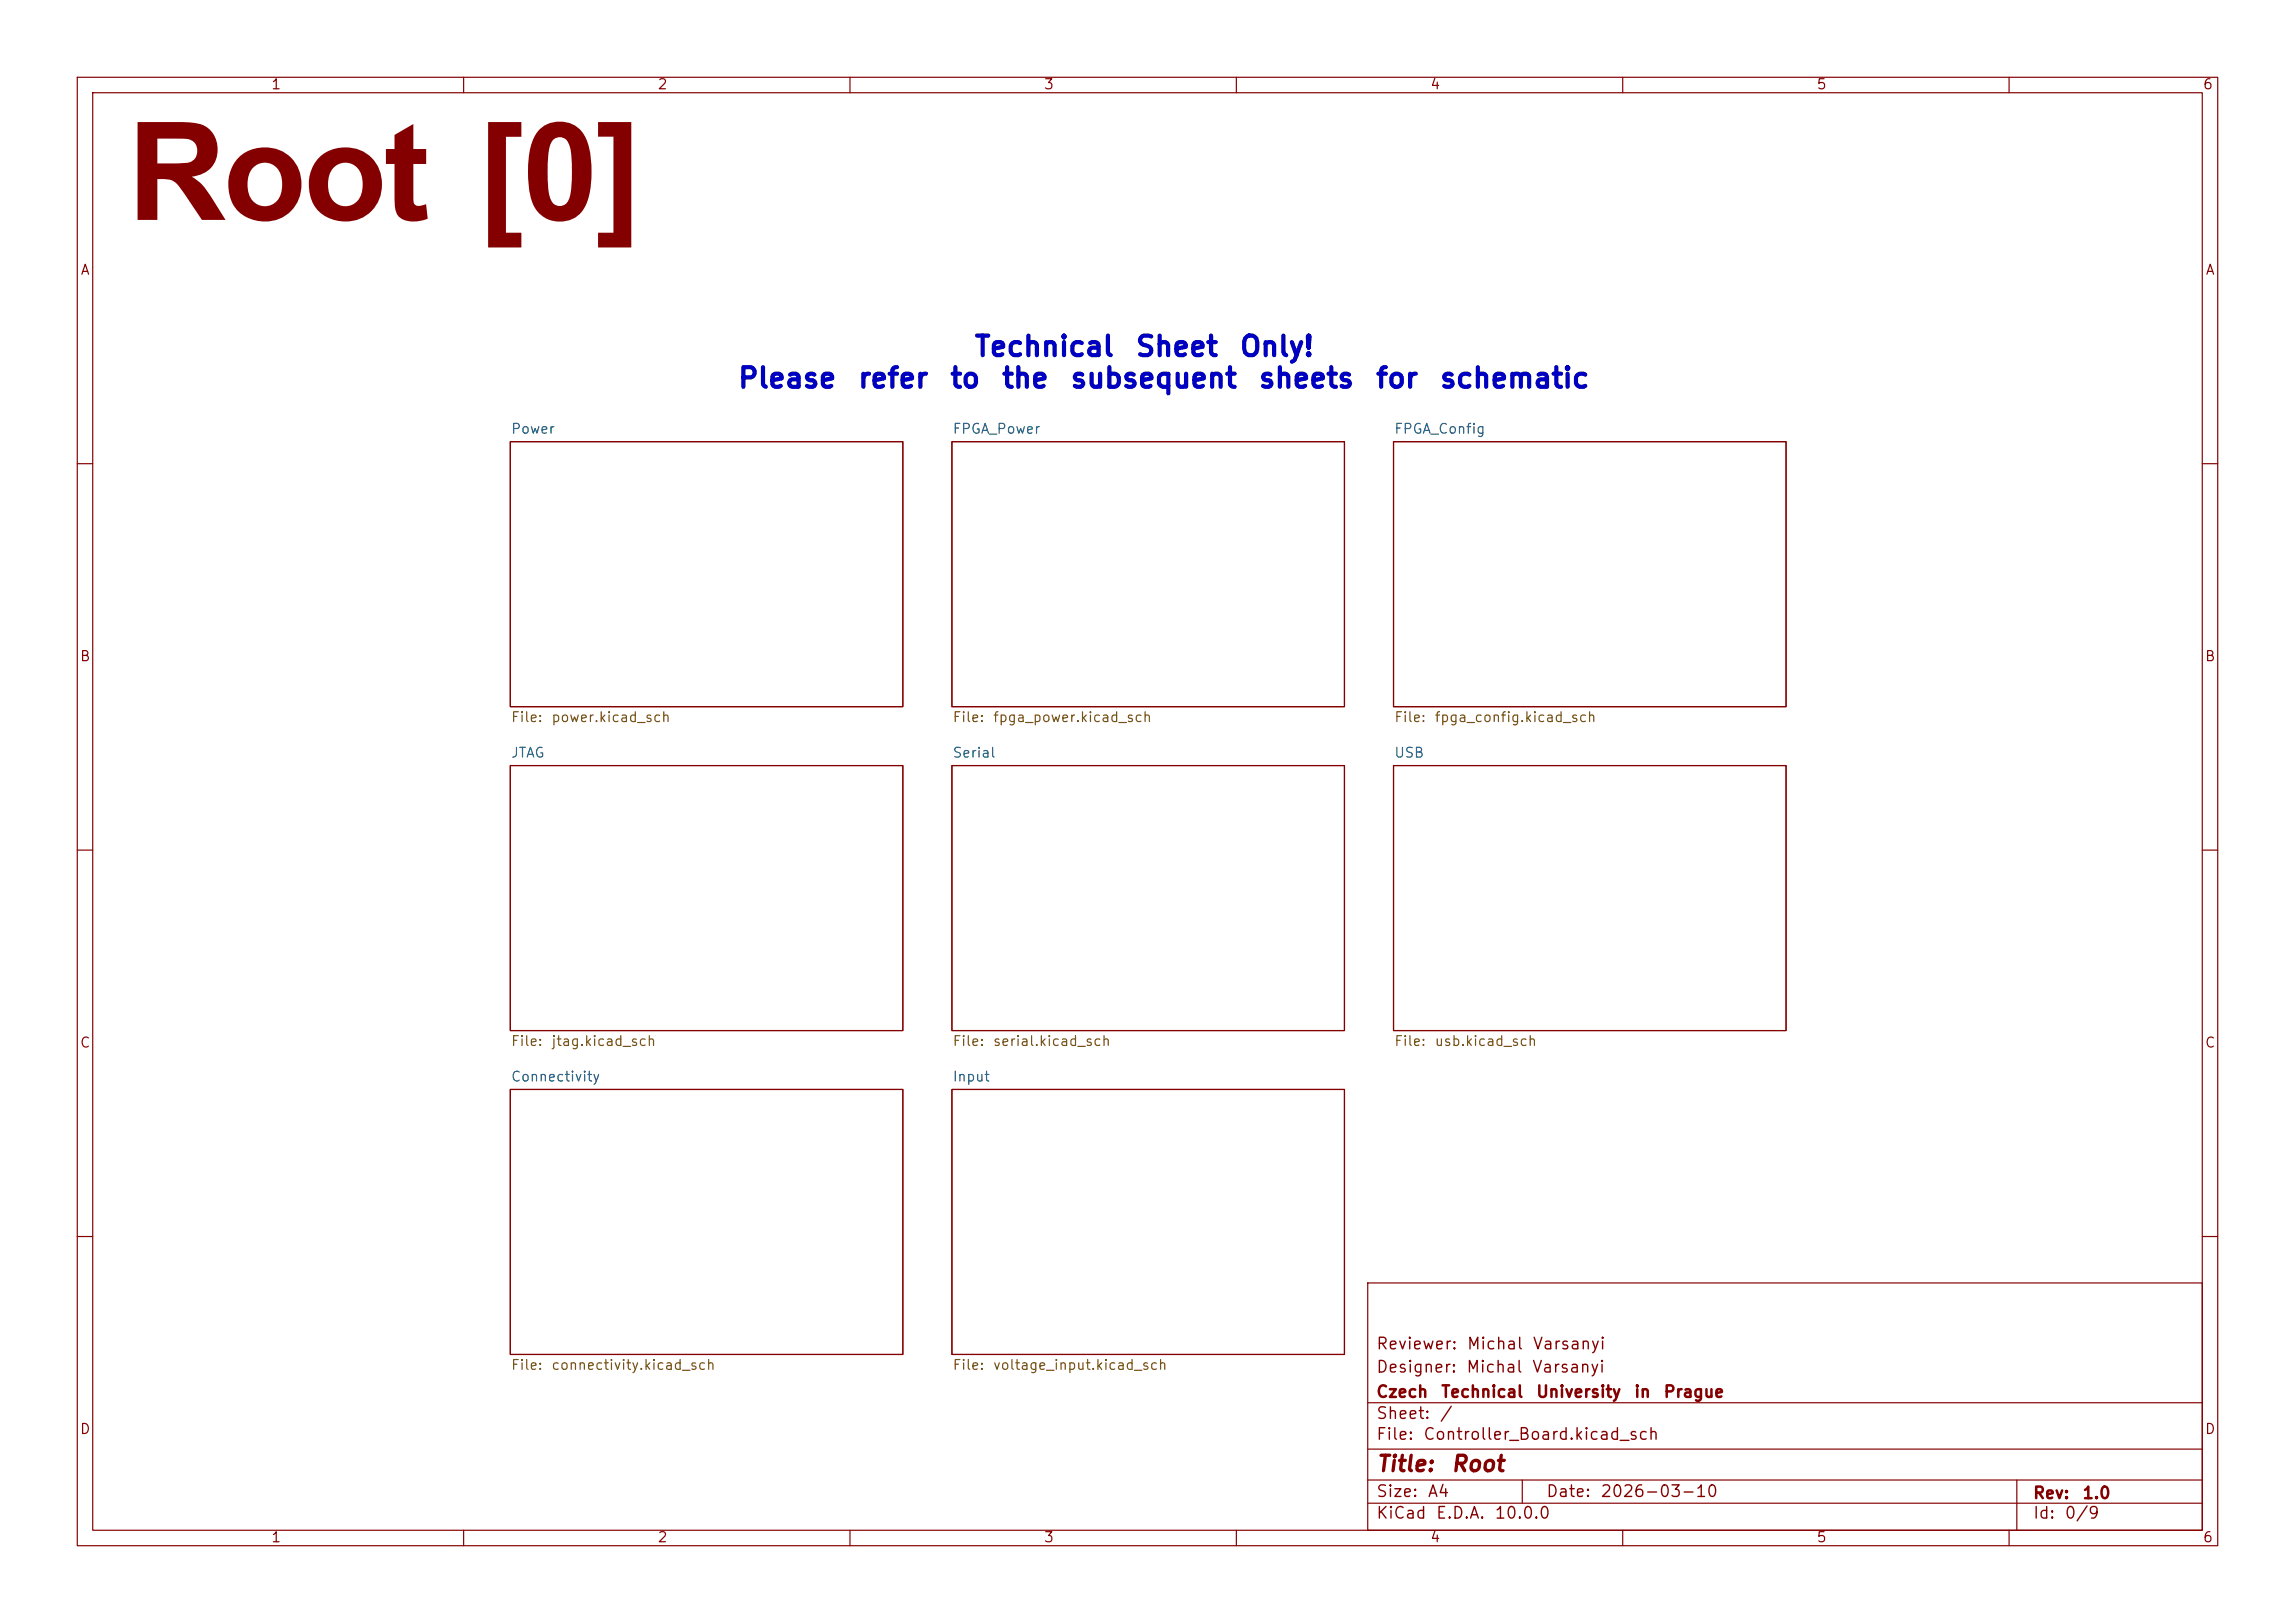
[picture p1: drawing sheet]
<svg xmlns="http://www.w3.org/2000/svg" width="297mm" height="210mm" viewBox="0 0 297 210" stroke-linecap="round" stroke-linejoin="round" font-family="sans-serif">
<defs><g id="words">
<text font-size="17.7" fill="#840000" x="16.5" y="28.5">Root [0]</text>
<g font-size="2.5" fill="#0000c2">
<text x="125.9" y="46.7">Technical</text>
<text x="146.8" y="46.7">Sheet</text>
<text x="160.3" y="46.7">Only!</text>
<text x="95.3" y="50.8">Please</text>
<text x="110.9" y="50.8">refer</text>
<text x="122.8" y="50.8">to</text>
<text x="129.5" y="50.8">the</text>
<text x="138.4" y="50.8">subsequent</text>
<text x="162.7" y="50.8">sheets</text>
<text x="177.9" y="50.8">for</text>
<text x="186.2" y="50.8">schematic</text>
</g>
<g font-size="2" fill="#840000">
<text x="178" y="190.9">Title:</text>
<text x="187.7" y="190.9">Root</text>
</g>
<g font-size="1.5" fill="#840000">
<text x="178" y="178">Designer:</text>
<text x="178" y="175">Reviewer:</text>
<text x="189.7" y="178">Michal</text>
<text x="189.7" y="175">Michal</text>
<text x="198.2" y="178">Varsanyi</text>
<text x="198.2" y="175">Varsanyi</text>
<text x="178" y="184">Sheet:</text>
<text x="178" y="181.2">Czech</text>
<text x="186.2" y="184">/</text>
<text x="186.4" y="181.2">Technical</text>
<text x="198.7" y="181.2">University</text>
<text x="211.4" y="181.2">in</text>
<text x="215.2" y="181.2">Prague</text>
<text x="178" y="186.7">File:</text>
<text x="184.1" y="186.7">Controller_Board.kicad_sch</text>
<text x="178" y="196.9">KiCad</text>
<text x="178" y="194.1">Size:</text>
<text x="184.7" y="194.1">A4</text>
<text x="185.7" y="196.9">E.D.A.</text>
<text x="193.3" y="196.9">10.0.0</text>
<text x="200" y="194.1">Date:</text>
<text x="207" y="194.1">2026-03-10</text>
<text x="263" y="194.3">Rev:</text>
<text x="263" y="196.9">Id:</text>
<text x="267.1" y="196.9">0/9</text>
<text x="269.4" y="194.3">1.0</text>
</g>
<g font-size="1.3" fill="#840000">
<text x="35" y="11.9">1</text>
<text x="85" y="11.9">2</text>
<text x="135" y="11.9">3</text>
<text x="185" y="11.9">4</text>
<text x="235" y="11.9">5</text>
<text x="285" y="11.9">6</text>
<text x="10.3" y="35.9">A</text>
<text x="285.3" y="35.9">A</text>
<text x="10.3" y="85.9">B</text>
<text x="285.3" y="85.9">B</text>
<text x="10.3" y="135.9">C</text>
<text x="285.3" y="135.9">C</text>
<text x="10.3" y="185.9">D</text>
<text x="285.3" y="185.9">D</text>
<text x="35" y="199.9">1</text>
<text x="85" y="199.9">2</text>
<text x="135" y="199.9">3</text>
<text x="185" y="199.9">4</text>
<text x="235" y="199.9">5</text>
<text x="285" y="199.9">6</text>
</g>
<g font-size="1.3" fill="#006464">
<text x="66" y="56.4">Power</text>
<text x="123.2" y="56.4">FPGA_Power</text>
<text x="180.3" y="56.4">FPGA_Config</text>
<text x="66" y="98.3">JTAG</text>
<text x="123.2" y="98.3">Serial</text>
<text x="180.3" y="98.3">USB</text>
<text x="66" y="140.3">Connectivity</text>
<text x="123.2" y="140.3">Input</text>
</g>
<g font-size="1.3" fill="#725600">
<text x="66" y="93.8">File:</text>
<text x="71.3" y="93.8">power.kicad_sch</text>
<text x="123.2" y="93.8">File:</text>
<text x="128.4" y="93.8">fpga_power.kicad_sch</text>
<text x="180.3" y="93.8">File:</text>
<text x="185.6" y="93.8">fpga_config.kicad_sch</text>
<text x="66" y="135.7">File:</text>
<text x="71.3" y="135.7">jtag.kicad_sch</text>
<text x="123.2" y="135.7">File:</text>
<text x="128.4" y="135.7">serial.kicad_sch</text>
<text x="180.3" y="135.7">File:</text>
<text x="185.6" y="135.7">usb.kicad_sch</text>
<text x="66" y="177.6">File:</text>
<text x="71.3" y="177.6">connectivity.kicad_sch</text>
<text x="123.2" y="177.6">File:</text>
<text x="128.4" y="177.6">voltage_input.kicad_sch</text>
</g>
</g></defs>
<g fill="none" stroke="#840000" stroke-width=".15">
<path d="M10 10h277v190h-277zM12 12h273v186h-273zM60 10v2M110 10v2M160 10v2M210 10v2M260 10v2M66 57.2h50.8v34.2h-50.8zM123.2 57.2h50.8v34.2h-50.8zM180.3 57.2h50.8v34.2h-50.8zM10 60h2M285 60h2"/>
<path d="M66 99.1h50.8v34.3h-50.8zM123.2 99.1h50.8v34.3h-50.8zM180.3 99.1h50.8v34.3h-50.8zM10 110h2M285 110h2M66 141h50.8v34.3h-50.8zM123.2 141h50.8v34.3h-50.8zM10 160h2M177 166h108v32h-108zM285 160h2M60 198v2M110 198v2"/>
<path d="M160 198v2M177 194.5h108M177 191.5h108M177 187.5h108M177 181.5h108M197 191.5v3M210 198v2M260 198v2M261 191.5v6.5"/>
</g>
<use href="#words"/>
</svg>
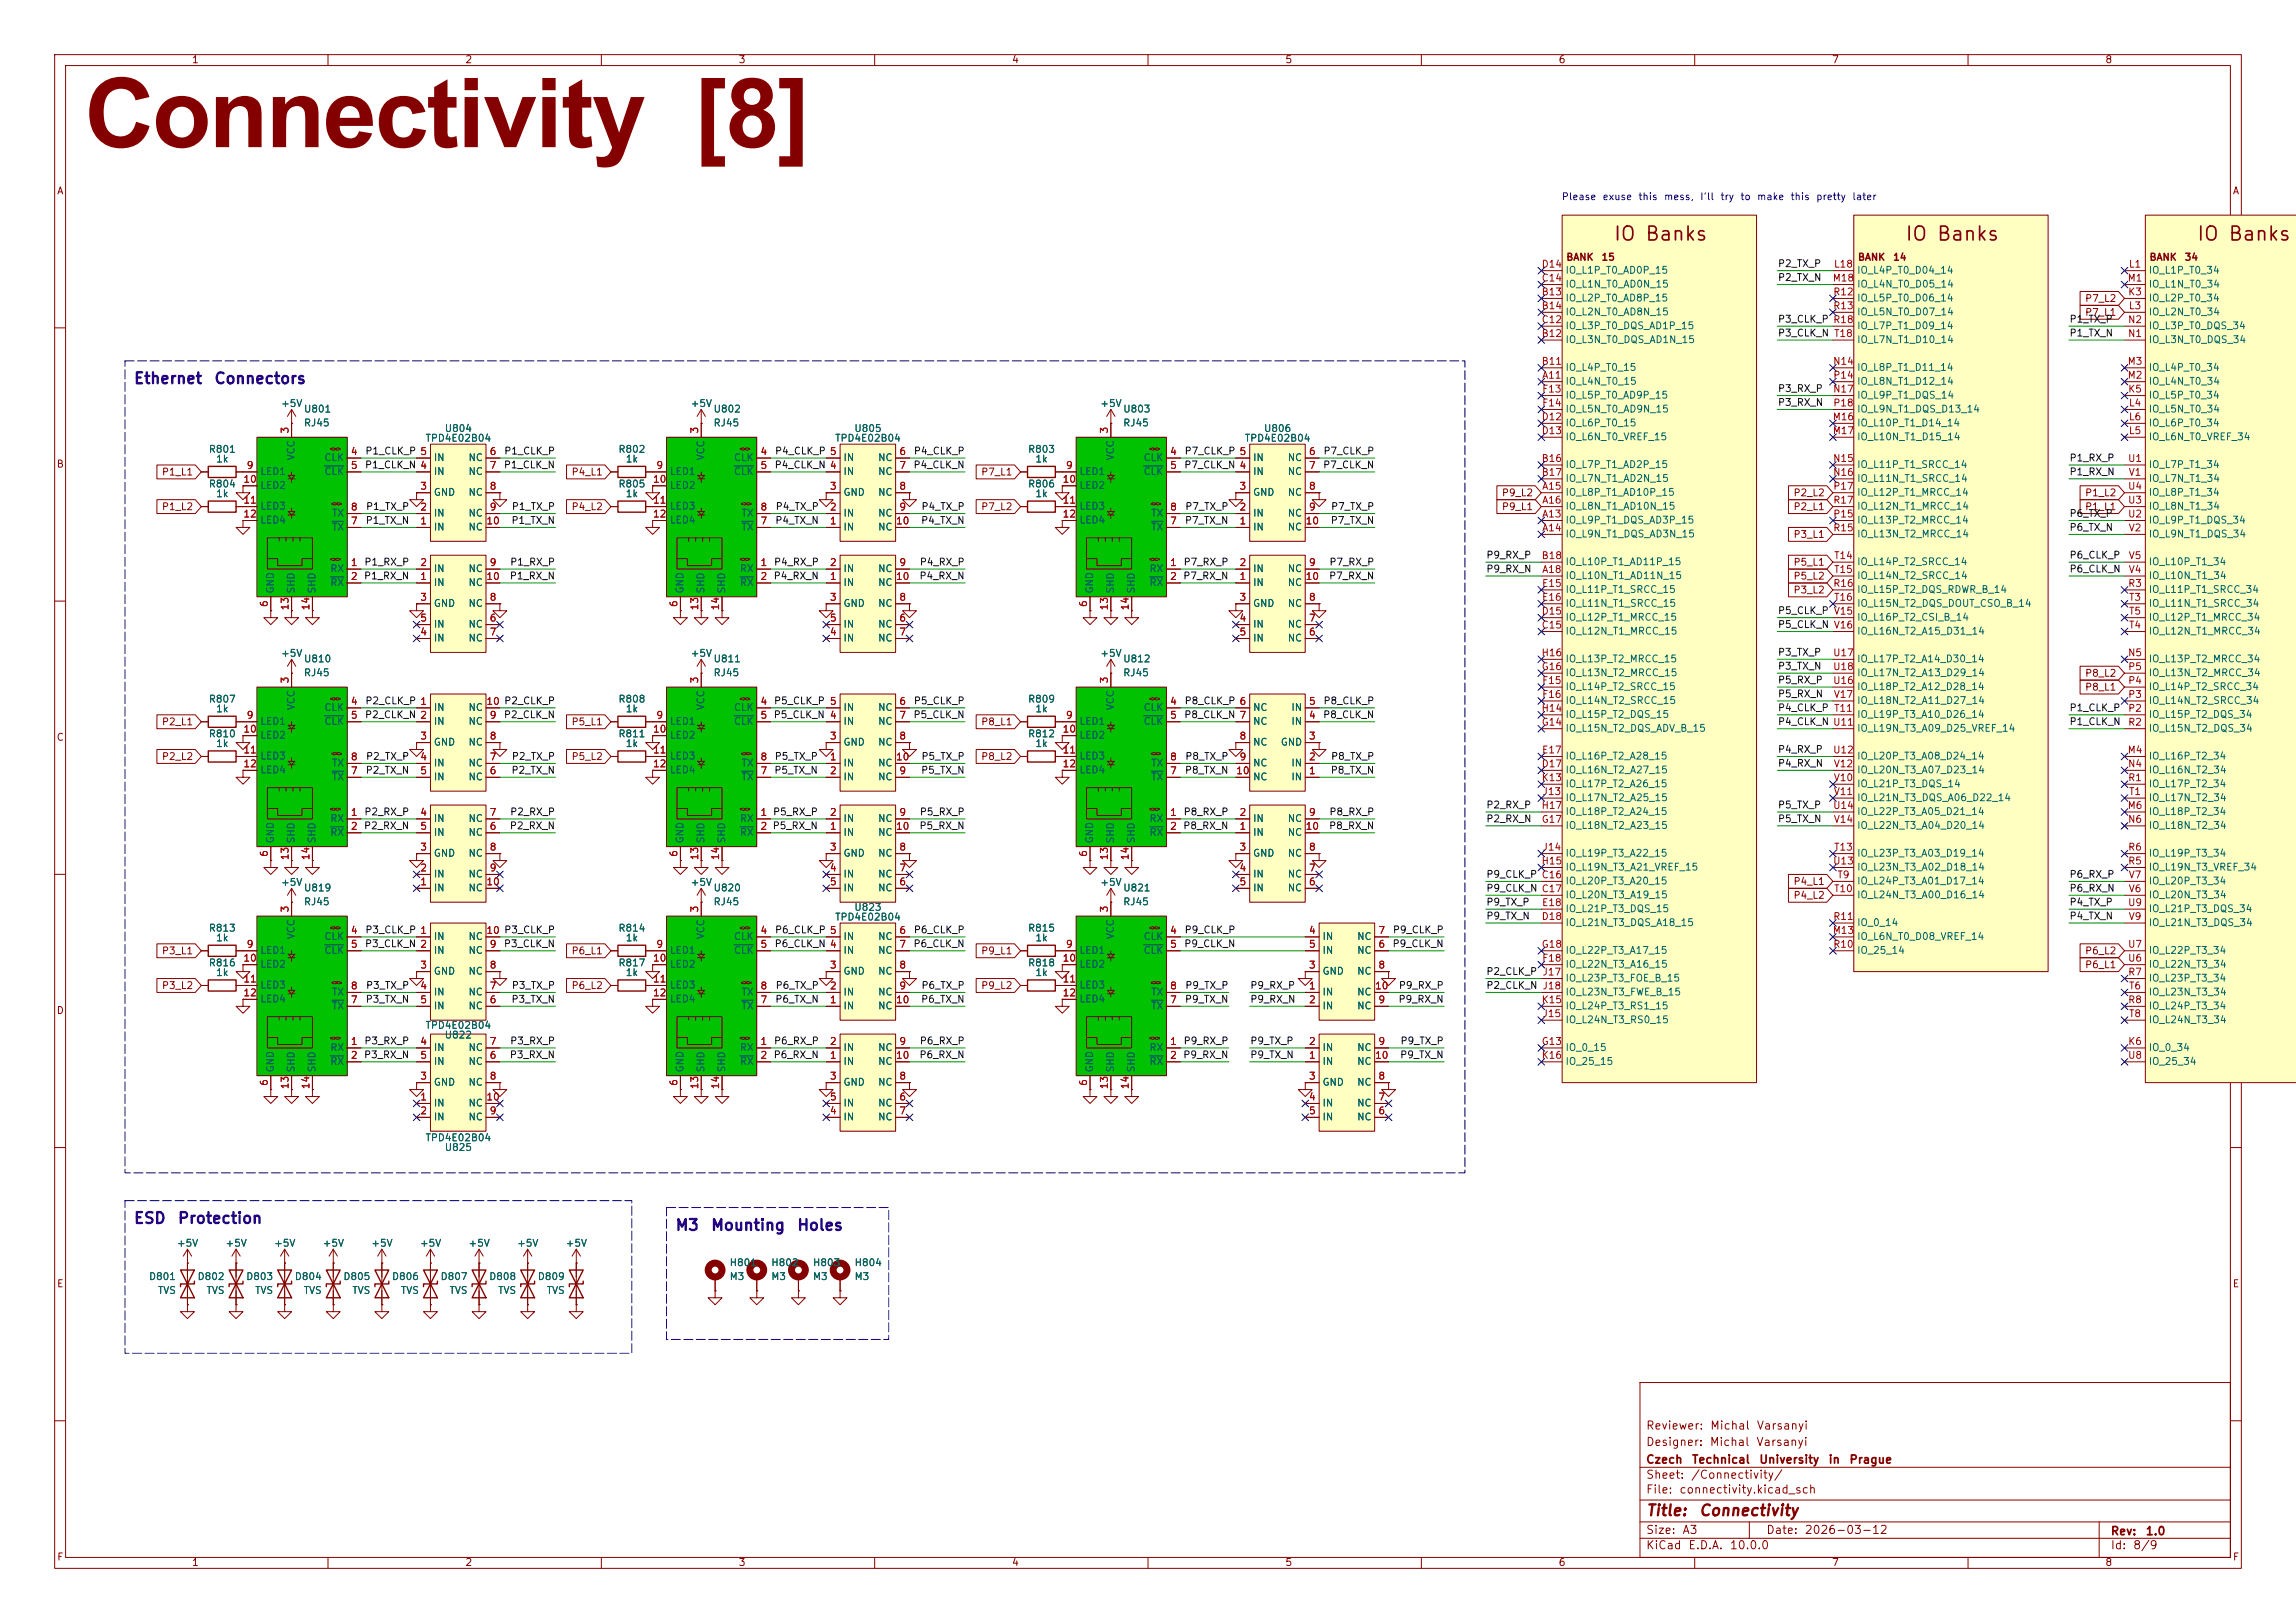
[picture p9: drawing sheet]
<svg xmlns="http://www.w3.org/2000/svg" width="420mm" height="297mm" viewBox="0 0 420 297" stroke-linecap="round" stroke-linejoin="round" font-family="sans-serif">
<defs><g id="words">
<text font-size="17.7" fill="#840000" x="15.5" y="26.9">Connectivity [8]</text>
<g font-size="2.5" fill="#840000">
<text x="295" y="44.7">IO</text>
<text x="300.8" y="44.7">Banks</text>
<text x="348.4" y="44.7">IO</text>
<text x="354.1" y="44.7">Banks</text>
<text x="401.7" y="44.7">IO</text>
<text x="407.5" y="44.7">Banks</text>
</g>
<g font-size="2" fill="#0000c2">
<text x="24.4" y="70.7">Ethernet</text>
<text x="39.1" y="70.7">Connectors</text>
<text x="24.4" y="224.4">ESD</text>
<text x="32.4" y="224.4">Protection</text>
<text x="123.4" y="225.7">M3</text>
<text x="129.9" y="225.7">Mounting</text>
<text x="145.7" y="225.7">Holes</text>
</g>
<g font-size="2" fill="#840000">
<text x="301" y="277.9">Title:</text>
<text x="310.6" y="277.9">Connectivity</text>
</g>
<g font-size="1.5" fill="#840000">
<text x="301" y="262">Reviewer:</text>
<text x="312.7" y="262">Michal</text>
<text x="321.2" y="262">Varsanyi</text>
<text x="301" y="268.2">Czech</text>
<text x="301" y="265">Designer:</text>
<text x="309.4" y="268.2">Technical</text>
<text x="312.6" y="265">Michal</text>
<text x="321.2" y="265">Varsanyi</text>
<text x="321.7" y="268.2">University</text>
<text x="334.4" y="268.2">in</text>
<text x="338.2" y="268.2">Prague</text>
<text x="301" y="273.7">File:</text>
<text x="301" y="271">Sheet:</text>
<text x="307.1" y="273.7">connectivity.kicad_sch</text>
<text x="309.2" y="271">/Connectivity/</text>
<text x="301" y="281.1">Size:</text>
<text x="307.6" y="281.1">A3</text>
<text x="323" y="281.1">Date:</text>
<text x="330" y="281.1">2026-03-12</text>
<text x="386" y="281.3">Rev:</text>
<text x="392.4" y="281.3">1.0</text>
<text x="301" y="283.9">KiCad</text>
<text x="308.7" y="283.9">E.D.A.</text>
<text x="316.3" y="283.9">10.0.0</text>
<text x="386" y="283.9">Id:</text>
<text x="390.1" y="283.9">8/9</text>
</g>
<g font-size="1.3" fill="#840000">
<text x="35" y="11.9">1</text>
<text x="85" y="11.9">2</text>
<text x="135" y="11.9">3</text>
<text x="185" y="11.9">4</text>
<text x="235" y="11.9">5</text>
<text x="285" y="11.9">6</text>
<text x="335" y="11.9">7</text>
<text x="385" y="11.9">8</text>
<text x="10.3" y="35.9">A</text>
<text x="408.3" y="35.9">A</text>
<text x="286.4" y="48">BANK</text>
<text x="292.8" y="48">15</text>
<text x="339.7" y="48">BANK</text>
<text x="346.2" y="48">14</text>
<text x="393.1" y="48">BANK</text>
<text x="399.5" y="48">34</text>
<text x="381.3" y="55.6">P7_L2</text>
<text x="381.3" y="58.1">P7_L1</text>
<text x="10.3" y="85.9">B</text>
<text x="29.5" y="87.3">P1_L1</text>
<text x="104.4" y="87.3">P4_L1</text>
<text x="179.4" y="87.3">P7_L1</text>
<text x="29.5" y="93.7">P1_L2</text>
<text x="104.4" y="93.7">P4_L2</text>
<text x="179.4" y="93.7">P7_L2</text>
<text x="274.6" y="91.1">P9_L2</text>
<text x="274.6" y="93.7">P9_L1</text>
<text x="328" y="93.7">P2_L1</text>
<text x="328" y="91.1">P2_L2</text>
<text x="381.3" y="91.1">P1_L2</text>
<text x="381.3" y="93.7">P1_L1</text>
<text x="328" y="98.7">P3_L1</text>
<text x="328" y="103.8">P5_L1</text>
<text x="328" y="106.4">P5_L2</text>
<text x="328" y="108.9">P3_L2</text>
<text x="381.3" y="124.1">P8_L2</text>
<text x="381.3" y="126.7">P8_L1</text>
<text x="10.3" y="135.9">C</text>
<text x="29.5" y="133">P2_L1</text>
<text x="104.4" y="133">P5_L1</text>
<text x="179.4" y="133">P8_L1</text>
<text x="408.2" y="135.9">C</text>
<text x="29.5" y="139.4">P2_L2</text>
<text x="104.4" y="139.4">P5_L2</text>
<text x="179.4" y="139.4">P8_L2</text>
<text x="328" y="164.8">P4_L2</text>
<text x="328" y="162.2">P4_L1</text>
<text x="29.5" y="174.9">P3_L1</text>
<text x="104.4" y="174.9">P6_L1</text>
<text x="179.4" y="174.9">P9_L1</text>
<text x="381.3" y="174.9">P6_L2</text>
<text x="381.3" y="177.5">P6_L1</text>
<text x="10.3" y="185.9">D</text>
<text x="29.5" y="181.3">P3_L2</text>
<text x="104.4" y="181.3">P6_L2</text>
<text x="179.4" y="181.3">P9_L2</text>
<text x="10.3" y="235.9">E</text>
<text x="408.3" y="235.9">E</text>
<text x="10.3" y="285.9">F</text>
<text x="35" y="286.9">1</text>
<text x="85" y="286.9">2</text>
<text x="135" y="286.9">3</text>
<text x="185" y="286.9">4</text>
<text x="235" y="286.9">5</text>
<text x="285" y="286.9">6</text>
<text x="335" y="286.9">7</text>
<text x="385" y="286.9">8</text>
<text x="408.3" y="285.9">F</text>
</g>
<g font-size="1.3" fill="#0000c2">
<text x="285.6" y="36.9">Please</text>
<text x="293" y="36.9">exuse</text>
<text x="299.6" y="36.9">this</text>
<text x="304.3" y="36.9">mess,</text>
<text x="310.9" y="36.9">I'll</text>
<text x="314.6" y="36.9">try</text>
<text x="318.2" y="36.9">to</text>
<text x="321.3" y="36.9">make</text>
<text x="327.4" y="36.9">this</text>
<text x="332.1" y="36.9">pretty</text>
<text x="338.7" y="36.9">later</text>
</g>
<g font-size="1.3" fill="#a90000">
<text x="281.9" y="51.8">C14</text>
<text x="281.9" y="49.3">D14</text>
<text x="335.1" y="51.8">M18</text>
<text x="335.4" y="49.3">L18</text>
<text x="389.1" y="51.8">M1</text>
<text x="389.3" y="49.3">L1</text>
<text x="281.9" y="54.4">B13</text>
<text x="281.9" y="56.9">B14</text>
<text x="281.9" y="59.4">C12</text>
<text x="335.2" y="54.4">R12</text>
<text x="335.2" y="56.9">R13</text>
<text x="389.2" y="59.4">N2</text>
<text x="389.2" y="54.4">K3</text>
<text x="389.3" y="56.9">L3</text>
<text x="281.9" y="62">B12</text>
<text x="335.4" y="62">T18</text>
<text x="389.2" y="62">N1</text>
<text x="281.9" y="67.1">B11</text>
<text x="282" y="69.6">A11</text>
<text x="335.2" y="67.1">N14</text>
<text x="335.2" y="69.6">P14</text>
<text x="389.1" y="69.6">M2</text>
<text x="389.1" y="67.1">M3</text>
<text x="281.9" y="77.2">D12</text>
<text x="282" y="72.1">F13</text>
<text x="282" y="74.7">F14</text>
<text x="335.1" y="77.2">M16</text>
<text x="335.2" y="72.1">N17</text>
<text x="335.2" y="74.7">P18</text>
<text x="389.2" y="72.1">K5</text>
<text x="389.3" y="74.7">L4</text>
<text x="389.3" y="77.2">L6</text>
<text x="53.1" y="79.4" transform="rotate(-90 53.1 79.4)">3</text>
<text x="64.1" y="83.6">4</text>
<text x="76.8" y="83.6">5</text>
<text x="89.5" y="83.6">6</text>
<text x="128" y="79.4" transform="rotate(-90 128 79.4)">3</text>
<text x="139" y="83.6">4</text>
<text x="151.7" y="83.6">5</text>
<text x="164.4" y="83.6">6</text>
<text x="202.9" y="79.4" transform="rotate(-90 202.9 79.4)">3</text>
<text x="213.9" y="83.6">4</text>
<text x="226.6" y="83.6">5</text>
<text x="239.3" y="83.6">6</text>
<text x="281.9" y="79.8">D13</text>
<text x="335.1" y="79.8">M17</text>
<text x="389.3" y="79.8">L5</text>
<text x="44.4" y="88.6">10</text>
<text x="45" y="86.1">9</text>
<text x="64.1" y="86.1">5</text>
<text x="76.8" y="89.9">3</text>
<text x="76.8" y="86.1">4</text>
<text x="89.5" y="86.1">7</text>
<text x="89.5" y="89.9">8</text>
<text x="119.3" y="88.6">10</text>
<text x="119.9" y="86.1">9</text>
<text x="139" y="86.1">5</text>
<text x="151.7" y="89.9">3</text>
<text x="151.7" y="86.1">4</text>
<text x="164.4" y="86.1">7</text>
<text x="164.4" y="89.9">8</text>
<text x="194.3" y="88.6">10</text>
<text x="194.9" y="86.1">9</text>
<text x="213.9" y="86.1">5</text>
<text x="226.6" y="89.9">3</text>
<text x="226.6" y="86.1">4</text>
<text x="239.3" y="86.1">7</text>
<text x="239.3" y="89.9">8</text>
<text x="281.9" y="84.8">B16</text>
<text x="281.9" y="87.4">B17</text>
<text x="282" y="89.9">A15</text>
<text x="335.2" y="84.8">N15</text>
<text x="335.2" y="87.4">N16</text>
<text x="335.2" y="89.9">P17</text>
<text x="389.2" y="84.8">U1</text>
<text x="389.2" y="89.9">U4</text>
<text x="389.3" y="87.4">V1</text>
<text x="44.4" y="92.5">11</text>
<text x="44.4" y="95">12</text>
<text x="64.1" y="93.7">8</text>
<text x="76.8" y="93.7">2</text>
<text x="89.5" y="93.7">9</text>
<text x="119.3" y="92.5">11</text>
<text x="119.3" y="95">12</text>
<text x="139" y="93.7">8</text>
<text x="151.7" y="93.7">2</text>
<text x="164.4" y="93.7">9</text>
<text x="194.3" y="92.5">11</text>
<text x="194.3" y="95">12</text>
<text x="213.9" y="93.7">8</text>
<text x="226.6" y="93.7">2</text>
<text x="239.3" y="93.7">9</text>
<text x="282" y="95">A13</text>
<text x="282" y="92.5">A16</text>
<text x="335.2" y="95">P15</text>
<text x="335.2" y="92.5">R17</text>
<text x="389.2" y="95">U2</text>
<text x="389.2" y="92.5">U3</text>
<text x="64.1" y="96.3">7</text>
<text x="76.8" y="96.3">1</text>
<text x="88.9" y="96.3">10</text>
<text x="139" y="96.3">7</text>
<text x="151.7" y="96.3">1</text>
<text x="163.8" y="96.3">10</text>
<text x="213.9" y="96.3">7</text>
<text x="226.6" y="96.3">1</text>
<text x="238.7" y="96.3">10</text>
<text x="282" y="97.5">A14</text>
<text x="335.2" y="97.5">R15</text>
<text x="389.3" y="97.5">V2</text>
<text x="64.1" y="103.9">1</text>
<text x="64.1" y="106.4">2</text>
<text x="76.8" y="106.4">1</text>
<text x="76.8" y="103.9">2</text>
<text x="88.9" y="106.4">10</text>
<text x="89.5" y="103.9">9</text>
<text x="139" y="103.9">1</text>
<text x="139" y="106.4">2</text>
<text x="151.7" y="106.4">1</text>
<text x="151.7" y="103.9">2</text>
<text x="163.8" y="106.4">10</text>
<text x="164.4" y="103.9">9</text>
<text x="213.9" y="103.9">1</text>
<text x="213.9" y="106.4">2</text>
<text x="226.6" y="106.4">1</text>
<text x="226.6" y="103.9">2</text>
<text x="238.7" y="106.4">10</text>
<text x="239.3" y="103.9">9</text>
<text x="281.9" y="102.6">B18</text>
<text x="282" y="107.7">E15</text>
<text x="282" y="105.2">A18</text>
<text x="335.2" y="107.7">R16</text>
<text x="335.4" y="102.6">T14</text>
<text x="335.4" y="105.2">T15</text>
<text x="389.2" y="107.7">R3</text>
<text x="389.3" y="105.2">V4</text>
<text x="389.3" y="102.6">V5</text>
<text x="49.3" y="111.2" transform="rotate(-90 49.3 111.2)">6</text>
<text x="53.1" y="111.8" transform="rotate(-90 53.1 111.8)">13</text>
<text x="56.9" y="111.8" transform="rotate(-90 56.9 111.8)">14</text>
<text x="76.8" y="110.2">3</text>
<text x="89.5" y="110.2">8</text>
<text x="124.2" y="111.2" transform="rotate(-90 124.2 111.2)">6</text>
<text x="128" y="111.8" transform="rotate(-90 128 111.8)">13</text>
<text x="131.8" y="111.8" transform="rotate(-90 131.8 111.8)">14</text>
<text x="151.7" y="110.2">3</text>
<text x="164.4" y="110.2">8</text>
<text x="199.1" y="111.2" transform="rotate(-90 199.1 111.2)">6</text>
<text x="202.9" y="111.8" transform="rotate(-90 202.9 111.8)">13</text>
<text x="206.8" y="111.8" transform="rotate(-90 206.8 111.8)">14</text>
<text x="226.6" y="110.2">3</text>
<text x="239.3" y="110.2">8</text>
<text x="281.9" y="112.8">D15</text>
<text x="282" y="110.2">E16</text>
<text x="335.3" y="112.8">V15</text>
<text x="335.4" y="110.2">T16</text>
<text x="389.3" y="110.2">T3</text>
<text x="389.3" y="112.8">T5</text>
<text x="76.8" y="116.6">4</text>
<text x="76.8" y="114">5</text>
<text x="89.5" y="114">6</text>
<text x="89.5" y="116.6">7</text>
<text x="151.7" y="116.6">4</text>
<text x="151.7" y="114">5</text>
<text x="164.4" y="114">6</text>
<text x="164.4" y="116.6">7</text>
<text x="226.6" y="114">4</text>
<text x="226.6" y="116.6">5</text>
<text x="239.3" y="116.6">6</text>
<text x="239.3" y="114">7</text>
<text x="281.9" y="115.3">C15</text>
<text x="335.3" y="115.3">V16</text>
<text x="389.3" y="115.3">T4</text>
<text x="53.1" y="125.2" transform="rotate(-90 53.1 125.2)">3</text>
<text x="128" y="125.2" transform="rotate(-90 128 125.2)">3</text>
<text x="202.9" y="125.2" transform="rotate(-90 202.9 125.2)">3</text>
<text x="281.9" y="120.4">H16</text>
<text x="281.9" y="122.9">G16</text>
<text x="282" y="125.5">F15</text>
<text x="335.2" y="125.5">U16</text>
<text x="335.2" y="120.4">U17</text>
<text x="335.2" y="122.9">U18</text>
<text x="389.2" y="120.4">N5</text>
<text x="389.2" y="125.5">P4</text>
<text x="389.2" y="122.9">P5</text>
<text x="45" y="131.8">9</text>
<text x="64.1" y="129.3">4</text>
<text x="64.1" y="131.8">5</text>
<text x="76.8" y="129.3">1</text>
<text x="76.8" y="131.8">2</text>
<text x="88.9" y="129.3">10 P2_CLK_P</text>
<text x="88.9" y="129.3">10</text>
<text x="89.5" y="131.8">9</text>
<text x="119.9" y="131.8">9</text>
<text x="139" y="129.3">4</text>
<text x="139" y="131.8">5</text>
<text x="151.7" y="131.8">4</text>
<text x="151.7" y="129.3">5</text>
<text x="164.4" y="129.3">6</text>
<text x="164.4" y="131.8">7</text>
<text x="194.9" y="131.8">9</text>
<text x="213.9" y="129.3">4</text>
<text x="213.9" y="131.8">5</text>
<text x="226.6" y="129.3">6</text>
<text x="226.6" y="131.8">7</text>
<text x="239.3" y="131.8">4</text>
<text x="239.3" y="129.3">5</text>
<text x="281.9" y="130.6">H14</text>
<text x="282" y="128">F16</text>
<text x="335.3" y="128">V17</text>
<text x="335.4" y="130.6">T11</text>
<text x="389.2" y="130.6">P2</text>
<text x="389.2" y="128">P3</text>
<text x="44.4" y="134.4">10</text>
<text x="76.8" y="135.6">3</text>
<text x="89.5" y="135.6">8</text>
<text x="119.3" y="134.4">10</text>
<text x="151.7" y="135.6">3</text>
<text x="164.4" y="135.6">8</text>
<text x="194.3" y="134.4">10</text>
<text x="226.6" y="135.6">8</text>
<text x="239.3" y="135.6">3</text>
<text x="281.9" y="133.1">G14</text>
<text x="389.2" y="133.1">R2</text>
<text x="44.4" y="138.2">11</text>
<text x="44.4" y="140.7">12</text>
<text x="64.1" y="142">7</text>
<text x="64.1" y="139.4">8</text>
<text x="76.8" y="139.4">4</text>
<text x="76.8" y="142">5</text>
<text x="89.5" y="142">6</text>
<text x="89.5" y="139.4">7</text>
<text x="119.3" y="138.2">11</text>
<text x="119.3" y="140.7">12</text>
<text x="139" y="142">7</text>
<text x="139" y="139.4">8</text>
<text x="151.7" y="139.4">1</text>
<text x="151.7" y="142">2</text>
<text x="163.8" y="139.4">10</text>
<text x="164.4" y="142">9</text>
<text x="194.3" y="138.2">11</text>
<text x="194.3" y="140.7">12</text>
<text x="213.9" y="142">7</text>
<text x="213.9" y="139.4">8</text>
<text x="226" y="142">10</text>
<text x="226.6" y="139.4">9</text>
<text x="239.3" y="142">1</text>
<text x="239.3" y="139.4">2</text>
<text x="281.9" y="140.7">D17</text>
<text x="281.9" y="143.3">K13</text>
<text x="282" y="138.2">E17</text>
<text x="335.2" y="138.2">U12</text>
<text x="335.3" y="143.3">V10</text>
<text x="335.3" y="140.7">V12</text>
<text x="389.1" y="138.2">M4</text>
<text x="389.2" y="140.7">N4</text>
<text x="389.2" y="143.3">R1</text>
<text x="64.1" y="149.6">1</text>
<text x="76.8" y="149.6">4</text>
<text x="89.5" y="149.6">7</text>
<text x="139" y="149.6">1</text>
<text x="151.7" y="149.6">2</text>
<text x="164.4" y="149.6">9</text>
<text x="213.9" y="149.6">1</text>
<text x="226.6" y="149.6">2</text>
<text x="239.3" y="149.6">9</text>
<text x="281.9" y="148.3">H17</text>
<text x="282.1" y="145.8">J13</text>
<text x="335.2" y="148.3">U14</text>
<text x="335.3" y="145.8">V11</text>
<text x="389.1" y="148.3">M6</text>
<text x="389.3" y="145.8">T1</text>
<text x="64.1" y="152.1">2</text>
<text x="76.8" y="156">3</text>
<text x="76.8" y="152.1">5</text>
<text x="89.5" y="152.1">6</text>
<text x="89.5" y="156">8</text>
<text x="139" y="152.1">2</text>
<text x="151.7" y="152.1">1</text>
<text x="151.7" y="156">3</text>
<text x="163.8" y="152.1">10</text>
<text x="164.4" y="156">8</text>
<text x="213.9" y="152.1">2</text>
<text x="226.6" y="152.1">1</text>
<text x="226.6" y="156">3</text>
<text x="238.7" y="152.1">10</text>
<text x="239.3" y="156">8</text>
<text x="281.9" y="150.9">G17</text>
<text x="282.1" y="156">J14</text>
<text x="335.3" y="150.9">V14</text>
<text x="335.4" y="156">T13</text>
<text x="389.2" y="150.9">N6</text>
<text x="389.2" y="156">R6</text>
<text x="49.3" y="156.9" transform="rotate(-90 49.3 156.9)">6</text>
<text x="53.1" y="157.5" transform="rotate(-90 53.1 157.5)">13</text>
<text x="56.9" y="157.5" transform="rotate(-90 56.9 157.5)">14</text>
<text x="76.8" y="159.8">2</text>
<text x="89.5" y="159.8">9</text>
<text x="124.2" y="156.9" transform="rotate(-90 124.2 156.9)">6</text>
<text x="128" y="157.5" transform="rotate(-90 128 157.5)">13</text>
<text x="131.8" y="157.5" transform="rotate(-90 131.8 157.5)">14</text>
<text x="151.7" y="159.8">4</text>
<text x="164.4" y="159.8">7</text>
<text x="199.1" y="156.9" transform="rotate(-90 199.1 156.9)">6</text>
<text x="202.9" y="157.5" transform="rotate(-90 202.9 157.5)">13</text>
<text x="206.8" y="157.5" transform="rotate(-90 206.8 157.5)">14</text>
<text x="226.6" y="159.8">4</text>
<text x="239.3" y="159.8">7</text>
<text x="281.9" y="158.5">H15</text>
<text x="335.2" y="158.5">U13</text>
<text x="336" y="161">T9</text>
<text x="389.2" y="158.5">R5</text>
<text x="389.3" y="161">V7</text>
<text x="53.1" y="167.1" transform="rotate(-90 53.1 167.1)">3</text>
<text x="76.8" y="162.3">1</text>
<text x="88.9" y="162.3">10</text>
<text x="128" y="167.1" transform="rotate(-90 128 167.1)">3</text>
<text x="151.7" y="162.3">5</text>
<text x="164.4" y="162.3">6</text>
<text x="202.9" y="167.1" transform="rotate(-90 202.9 167.1)">3</text>
<text x="226.6" y="162.3">5</text>
<text x="239.3" y="162.3">6</text>
<text x="282" y="166.1">E18</text>
<text x="335.4" y="163.6">T10</text>
<text x="389.2" y="166.1">U9</text>
<text x="389.3" y="163.6">V6</text>
<text x="45" y="173.7">9</text>
<text x="64.1" y="171.2">4</text>
<text x="64.1" y="173.7">5</text>
<text x="76.8" y="171.2">1</text>
<text x="76.8" y="173.7">2</text>
<text x="88.9" y="171.2">10 P3_CLK_P</text>
<text x="88.9" y="171.2">10</text>
<text x="89.5" y="173.7">9</text>
<text x="119.9" y="173.7">9</text>
<text x="139" y="171.2">4</text>
<text x="139" y="173.7">5</text>
<text x="151.7" y="173.7">4</text>
<text x="151.7" y="171.2">5</text>
<text x="164.4" y="171.2">6</text>
<text x="164.4" y="173.7">7</text>
<text x="194.9" y="173.7">9</text>
<text x="213.9" y="171.2">4</text>
<text x="213.9" y="173.7">5</text>
<text x="239.3" y="171.2">4</text>
<text x="239.3" y="173.7">5</text>
<text x="252" y="173.7">6</text>
<text x="252" y="171.2">7</text>
<text x="281.9" y="168.7">D18</text>
<text x="281.9" y="173.7">G18</text>
<text x="335.1" y="171.2">M13</text>
<text x="335.2" y="173.7">R10</text>
<text x="335.2" y="168.7">R11</text>
<text x="389.2" y="173.7">U7</text>
<text x="389.3" y="168.7">V9</text>
<text x="44.4" y="176.3">10</text>
<text x="76.8" y="177.5">3</text>
<text x="89.5" y="177.5">8</text>
<text x="119.3" y="176.3">10</text>
<text x="151.7" y="177.5">3</text>
<text x="164.4" y="177.5">8</text>
<text x="194.3" y="176.3">10</text>
<text x="239.3" y="177.5">3</text>
<text x="252" y="177.5">8</text>
<text x="282" y="176.3">F18</text>
<text x="282.1" y="178.8">J17</text>
<text x="389.2" y="176.3">U6</text>
<text x="389.2" y="178.8">R7</text>
<text x="44.4" y="180.1">11</text>
<text x="44.4" y="182.6">12</text>
<text x="64.1" y="183.9">7</text>
<text x="64.1" y="181.4">8</text>
<text x="76.8" y="181.4">4</text>
<text x="76.8" y="183.9">5</text>
<text x="89.5" y="183.9">6</text>
<text x="89.5" y="181.4">7</text>
<text x="119.3" y="180.1">11</text>
<text x="119.3" y="182.6">12</text>
<text x="139" y="183.9">7</text>
<text x="139" y="181.4">8</text>
<text x="151.7" y="183.9">1</text>
<text x="151.7" y="181.4">2</text>
<text x="163.8" y="183.9">10</text>
<text x="164.4" y="181.4">9</text>
<text x="194.3" y="180.1">11</text>
<text x="194.3" y="182.6">12</text>
<text x="213.9" y="183.9">7</text>
<text x="213.9" y="181.4">8</text>
<text x="239.3" y="181.4">1</text>
<text x="239.3" y="183.9">2</text>
<text x="251.4" y="181.4">10</text>
<text x="252" y="183.9">9</text>
<text x="281.9" y="183.9">K15</text>
<text x="282.1" y="181.4">J18</text>
<text x="389.2" y="183.9">R8</text>
<text x="389.3" y="181.4">T6</text>
<text x="64.1" y="191.5">1</text>
<text x="76.8" y="191.5">4</text>
<text x="89.5" y="191.5">7</text>
<text x="139" y="191.5">1</text>
<text x="151.7" y="191.5">2</text>
<text x="164.4" y="191.5">9</text>
<text x="213.9" y="191.5">1</text>
<text x="239.3" y="191.5">2</text>
<text x="252" y="191.5">9</text>
<text x="281.9" y="191.5">G13</text>
<text x="282.1" y="186.4">J15</text>
<text x="389.2" y="191.5">K6</text>
<text x="389.3" y="186.4">T8</text>
<text x="64.1" y="194.1">2</text>
<text x="76.8" y="197.9">3</text>
<text x="76.8" y="194.1">5</text>
<text x="89.5" y="194.1">6</text>
<text x="89.5" y="197.9">8</text>
<text x="139" y="194.1">2</text>
<text x="151.7" y="194.1">1</text>
<text x="151.7" y="197.9">3</text>
<text x="163.8" y="194.1">10</text>
<text x="164.4" y="197.9">8</text>
<text x="213.9" y="194.1">2</text>
<text x="239.3" y="194.1">1</text>
<text x="239.3" y="197.9">3</text>
<text x="251.4" y="194.1">10</text>
<text x="252" y="197.9">8</text>
<text x="281.9" y="194.1">K16</text>
<text x="389.2" y="194.1">U8</text>
<text x="49.3" y="198.8" transform="rotate(-90 49.3 198.8)">6</text>
<text x="53.1" y="199.4" transform="rotate(-90 53.1 199.4)">13</text>
<text x="56.9" y="199.4" transform="rotate(-90 56.9 199.4)">14</text>
<text x="76.8" y="201.7">1</text>
<text x="88.9" y="201.7">10</text>
<text x="124.2" y="198.8" transform="rotate(-90 124.2 198.8)">6</text>
<text x="128" y="199.4" transform="rotate(-90 128 199.4)">13</text>
<text x="131.8" y="199.4" transform="rotate(-90 131.8 199.4)">14</text>
<text x="151.7" y="201.7">5</text>
<text x="164.4" y="201.7">6</text>
<text x="199.1" y="198.8" transform="rotate(-90 199.1 198.8)">6</text>
<text x="202.9" y="199.4" transform="rotate(-90 202.9 199.4)">13</text>
<text x="206.8" y="199.4" transform="rotate(-90 206.8 199.4)">14</text>
<text x="239.3" y="201.7">4</text>
<text x="252" y="201.7">7</text>
<text x="76.8" y="204.2">2</text>
<text x="89.5" y="204.2">9</text>
<text x="151.7" y="204.2">4</text>
<text x="164.4" y="204.2">7</text>
<text x="239.3" y="204.2">5</text>
<text x="252" y="204.2">6</text>
</g>
<g font-size="1.3" fill="#006464">
<text x="286.3" y="52.9">IO_L1N_T0_AD0N_15</text>
<text x="286.3" y="50.4">IO_L1P_T0_AD0P_15</text>
<text x="339.6" y="50.4">IO_L4P_T0_D04_14</text>
<text x="339.6" y="52.9">IO_L4N_T0_D05_14</text>
<text x="392.9" y="50.4">IO_L1P_T0_34</text>
<text x="392.9" y="52.9">IO_L1N_T0_34</text>
<text x="286.3" y="55.5">IO_L2P_T0_AD8P_15</text>
<text x="286.3" y="58">IO_L2N_T0_AD8N_15</text>
<text x="339.6" y="55.5">IO_L5P_T0_D06_14</text>
<text x="339.6" y="58">IO_L5N_T0_D07_14</text>
<text x="392.9" y="55.5">IO_L2P_T0_34</text>
<text x="392.9" y="58">IO_L2N_T0_34</text>
<text x="286.3" y="63.1">IO_L3N_T0_DQS_AD1N_15</text>
<text x="286.3" y="60.6">IO_L3P_T0_DQS_AD1P_15</text>
<text x="339.6" y="60.6">IO_L7P_T1_D09_14</text>
<text x="339.6" y="63.1">IO_L7N_T1_D10_14</text>
<text x="392.9" y="63.1">IO_L3N_T0_DQS_34</text>
<text x="392.9" y="60.6">IO_L3P_T0_DQS_34</text>
<text x="286.3" y="70.7">IO_L4N_T0_15</text>
<text x="286.3" y="68.2">IO_L4P_T0_15</text>
<text x="339.6" y="68.2">IO_L8P_T1_D11_14</text>
<text x="339.6" y="70.7">IO_L8N_T1_D12_14</text>
<text x="392.9" y="70.7">IO_L4N_T0_34</text>
<text x="392.9" y="68.2">IO_L4P_T0_34</text>
<text x="51.3" y="74.8">+5V</text>
<text x="55.5" y="75.8">U801</text>
<text x="126.2" y="74.8">+5V</text>
<text x="130.4" y="75.8">U802</text>
<text x="201.2" y="74.8">+5V</text>
<text x="205.4" y="75.8">U803</text>
<text x="286.3" y="73.3">IO_L5P_T0_AD9P_15</text>
<text x="286.3" y="75.8">IO_L5N_T0_AD9N_15</text>
<text x="339.6" y="73.3">IO_L9P_T1_DQS_14</text>
<text x="339.6" y="75.8">IO_L9N_T1_DQS_D13_14</text>
<text x="392.9" y="73.3">IO_L5P_T0_34</text>
<text x="392.9" y="75.8">IO_L5N_T0_34</text>
<text x="38.1" y="83.2">R801</text>
<text x="55.5" y="78.3">RJ45</text>
<text x="77.7" y="81.1">TPD4E02B04</text>
<text x="81.2" y="79.3">U804</text>
<text x="113" y="83.2">R802</text>
<text x="130.4" y="78.3">RJ45</text>
<text x="152.7" y="81.1">TPD4E02B04</text>
<text x="156.2" y="79.3">U805</text>
<text x="187.9" y="83.2">R803</text>
<text x="205.4" y="78.3">RJ45</text>
<text x="227.6" y="81.1">TPD4E02B04</text>
<text x="231.1" y="79.3">U806</text>
<text x="286.3" y="78.3">IO_L6P_T0_15</text>
<text x="286.3" y="80.9">IO_L6N_T0_VREF_15</text>
<text x="339.6" y="78.3">IO_L10P_T1_D14_14</text>
<text x="339.6" y="80.9">IO_L10N_T1_D15_14</text>
<text x="392.9" y="80.9">IO_L6N_T0_VREF_34</text>
<text x="392.9" y="78.3">IO_L6P_T0_34</text>
<text x="38.1" y="89.5">R804</text>
<text x="39.4" y="84.9">1k</text>
<text x="47.5" y="87.2">LED1</text>
<text x="47.5" y="89.8">LED2</text>
<text x="54.2" y="84.3" transform="rotate(-90 54.2 84.3)">VCC</text>
<text x="59.2" y="84.7">CLK</text>
<text x="59.2" y="87.2">CLK</text>
<text x="79.2" y="87.2">IN</text>
<text x="79.2" y="84.7">IN</text>
<text x="85.6" y="84.7">NC</text>
<text x="85.6" y="87.2">NC</text>
<text x="113" y="89.5">R805</text>
<text x="114.3" y="84.9">1k</text>
<text x="122.4" y="87.2">LED1</text>
<text x="122.4" y="89.8">LED2</text>
<text x="129.1" y="84.3" transform="rotate(-90 129.1 84.3)">VCC</text>
<text x="134.2" y="84.7">CLK</text>
<text x="134.2" y="87.2">CLK</text>
<text x="154.2" y="87.2">IN</text>
<text x="154.2" y="84.7">IN</text>
<text x="160.5" y="84.7">NC</text>
<text x="160.5" y="87.2">NC</text>
<text x="187.9" y="89.5">R806</text>
<text x="189.3" y="84.9">1k</text>
<text x="197.4" y="87.2">LED1</text>
<text x="197.4" y="89.8">LED2</text>
<text x="204.1" y="84.3" transform="rotate(-90 204.1 84.3)">VCC</text>
<text x="209.1" y="84.7">CLK</text>
<text x="209.1" y="87.2">CLK</text>
<text x="229.1" y="87.2">IN</text>
<text x="229.1" y="84.7">IN</text>
<text x="235.4" y="84.7">NC</text>
<text x="235.4" y="87.2">NC</text>
<text x="286.3" y="86">IO_L7P_T1_AD2P_15</text>
<text x="286.3" y="88.5">IO_L7N_T1_AD2N_15</text>
<text x="339.6" y="86">IO_L11P_T1_SRCC_14</text>
<text x="339.6" y="88.5">IO_L11N_T1_SRCC_14</text>
<text x="392.9" y="86">IO_L7P_T1_34</text>
<text x="392.9" y="88.5">IO_L7N_T1_34</text>
<text x="39.4" y="91.3">1k</text>
<text x="47.5" y="93.6">LED3</text>
<text x="60.6" y="94.8">TX</text>
<text x="79.2" y="94.8">IN</text>
<text x="79.2" y="91">GND</text>
<text x="85.6" y="91">NC</text>
<text x="85.6" y="94.8">NC</text>
<text x="114.3" y="91.3">1k</text>
<text x="122.4" y="93.6">LED3</text>
<text x="135.5" y="94.8">TX</text>
<text x="154.2" y="94.8">IN</text>
<text x="154.2" y="91">GND</text>
<text x="160.5" y="91">NC</text>
<text x="160.5" y="94.8">NC</text>
<text x="189.3" y="91.3">1k</text>
<text x="197.4" y="93.6">LED3</text>
<text x="210.5" y="94.8">TX</text>
<text x="229.1" y="94.8">IN</text>
<text x="229.1" y="91">GND</text>
<text x="235.4" y="91">NC</text>
<text x="235.4" y="94.8">NC</text>
<text x="286.3" y="91">IO_L8P_T1_AD10P_15</text>
<text x="286.3" y="93.6">IO_L8N_T1_AD10N_15</text>
<text x="339.6" y="91">IO_L12P_T1_MRCC_14</text>
<text x="339.6" y="93.6">IO_L12N_T1_MRCC_14</text>
<text x="392.9" y="93.6">IO_L8N_T1_34</text>
<text x="392.9" y="91">IO_L8P_T1_34</text>
<text x="47.5" y="96.1">LED4</text>
<text x="60.6" y="97.4">TX</text>
<text x="79.2" y="97.4">IN</text>
<text x="85.6" y="97.4">NC</text>
<text x="122.4" y="96.1">LED4</text>
<text x="135.5" y="97.4">TX</text>
<text x="154.2" y="97.4">IN</text>
<text x="160.5" y="97.4">NC</text>
<text x="197.4" y="96.1">LED4</text>
<text x="210.5" y="97.4">TX</text>
<text x="229.1" y="97.4">IN</text>
<text x="235.4" y="97.4">NC</text>
<text x="286.3" y="96.1">IO_L9P_T1_DQS_AD3P_15</text>
<text x="286.3" y="98.7">IO_L9N_T1_DQS_AD3N_15</text>
<text x="339.6" y="96.1">IO_L13P_T2_MRCC_14</text>
<text x="339.6" y="98.7">IO_L13N_T2_MRCC_14</text>
<text x="392.9" y="96.1">IO_L9P_T1_DQS_34</text>
<text x="392.9" y="98.7">IO_L9N_T1_DQS_34</text>
<text x="60.3" y="105">RX</text>
<text x="60.3" y="107.5">RX</text>
<text x="79.2" y="107.5">IN</text>
<text x="79.2" y="105">IN</text>
<text x="85.6" y="105">NC</text>
<text x="85.6" y="107.5">NC</text>
<text x="135.2" y="105">RX</text>
<text x="135.2" y="107.5">RX</text>
<text x="154.2" y="107.5">IN</text>
<text x="154.2" y="105">IN</text>
<text x="160.5" y="105">NC</text>
<text x="160.5" y="107.5">NC</text>
<text x="210.2" y="105">RX</text>
<text x="210.2" y="107.5">RX</text>
<text x="229.1" y="107.5">IN</text>
<text x="229.1" y="105">IN</text>
<text x="235.4" y="105">NC</text>
<text x="235.4" y="107.5">NC</text>
<text x="286.3" y="106.3">IO_L10N_T1_AD11N_15</text>
<text x="286.3" y="103.7">IO_L10P_T1_AD11P_15</text>
<text x="339.6" y="103.7">IO_L14P_T2_SRCC_14</text>
<text x="339.6" y="106.3">IO_L14N_T2_SRCC_14</text>
<text x="392.9" y="106.3">IO_L10N_T1_34</text>
<text x="392.9" y="103.7">IO_L10P_T1_34</text>
<text x="50.4" y="108.7" transform="rotate(-90 50.4 108.7)">GND</text>
<text x="54.2" y="108.7" transform="rotate(-90 54.2 108.7)">SHD</text>
<text x="58" y="108.7" transform="rotate(-90 58 108.7)">SHD</text>
<text x="79.2" y="111.4">GND</text>
<text x="85.6" y="111.4">NC</text>
<text x="125.3" y="108.7" transform="rotate(-90 125.3 108.7)">GND</text>
<text x="129.1" y="108.7" transform="rotate(-90 129.1 108.7)">SHD</text>
<text x="132.9" y="108.7" transform="rotate(-90 132.9 108.7)">SHD</text>
<text x="154.2" y="111.4">GND</text>
<text x="160.5" y="111.4">NC</text>
<text x="200.3" y="108.7" transform="rotate(-90 200.3 108.7)">GND</text>
<text x="204.1" y="108.7" transform="rotate(-90 204.1 108.7)">SHD</text>
<text x="207.9" y="108.7" transform="rotate(-90 207.9 108.7)">SHD</text>
<text x="229.1" y="111.4">GND</text>
<text x="235.4" y="111.4">NC</text>
<text x="286.3" y="113.9">IO_L12P_T1_MRCC_15</text>
<text x="286.3" y="108.8">IO_L11P_T1_SRCC_15</text>
<text x="286.3" y="111.4">IO_L11N_T1_SRCC_15</text>
<text x="339.6" y="108.8">IO_L15P_T2_DQS_RDWR_B_14</text>
<text x="339.6" y="111.4">IO_L15N_T2_DQS_DOUT_CSO_B_14</text>
<text x="339.6" y="113.9">IO_L16P_T2_CSI_B_14</text>
<text x="392.9" y="108.8">IO_L11P_T1_SRCC_34</text>
<text x="392.9" y="111.4">IO_L11N_T1_SRCC_34</text>
<text x="392.9" y="113.9">IO_L12P_T1_MRCC_34</text>
<text x="79.2" y="117.7">IN</text>
<text x="79.2" y="115.2">IN</text>
<text x="85.6" y="115.2">NC</text>
<text x="85.6" y="117.7">NC</text>
<text x="154.2" y="117.7">IN</text>
<text x="154.2" y="115.2">IN</text>
<text x="160.5" y="115.2">NC</text>
<text x="160.5" y="117.7">NC</text>
<text x="229.1" y="115.2">IN</text>
<text x="229.1" y="117.7">IN</text>
<text x="235.4" y="117.7">NC</text>
<text x="235.4" y="115.2">NC</text>
<text x="286.3" y="116.4">IO_L12N_T1_MRCC_15</text>
<text x="339.6" y="116.4">IO_L16N_T2_A15_D31_14</text>
<text x="392.9" y="116.4">IO_L12N_T1_MRCC_34</text>
<text x="51.3" y="120.5">+5V</text>
<text x="55.5" y="121.5">U810</text>
<text x="55.5" y="124.1">RJ45</text>
<text x="126.2" y="120.5">+5V</text>
<text x="130.4" y="121.5">U811</text>
<text x="130.4" y="124.1">RJ45</text>
<text x="201.2" y="120.5">+5V</text>
<text x="205.4" y="121.5">U812</text>
<text x="205.4" y="124.1">RJ45</text>
<text x="286.3" y="124.1">IO_L13N_T2_MRCC_15</text>
<text x="286.3" y="121.5">IO_L13P_T2_MRCC_15</text>
<text x="339.6" y="121.5">IO_L17P_T2_A14_D30_14</text>
<text x="339.6" y="124.1">IO_L17N_T2_A13_D29_14</text>
<text x="392.9" y="121.5">IO_L13P_T2_MRCC_34</text>
<text x="392.9" y="124.1">IO_L13N_T2_MRCC_34</text>
<text x="38.1" y="128.9">R807</text>
<text x="39.4" y="130.7">1k</text>
<text x="54.2" y="130.1" transform="rotate(-90 54.2 130.1)">VCC</text>
<text x="59.2" y="130.4">CLK</text>
<text x="79.2" y="130.4">IN</text>
<text x="85.6" y="130.4">NC</text>
<text x="113" y="128.9">R808</text>
<text x="114.3" y="130.7">1k</text>
<text x="129.1" y="130.1" transform="rotate(-90 129.1 130.1)">VCC</text>
<text x="134.2" y="130.4">CLK</text>
<text x="154.2" y="130.4">IN</text>
<text x="160.5" y="130.4">NC</text>
<text x="187.9" y="128.9">R809</text>
<text x="189.3" y="130.7">1k</text>
<text x="204.1" y="130.1" transform="rotate(-90 204.1 130.1)">VCC</text>
<text x="209.1" y="130.4">CLK</text>
<text x="229.1" y="130.4">NC</text>
<text x="236.1" y="130.4">IN</text>
<text x="286.3" y="126.6">IO_L14P_T2_SRCC_15</text>
<text x="286.3" y="129.1">IO_L14N_T2_SRCC_15</text>
<text x="286.3" y="131.7">IO_L15P_T2_DQS_15</text>
<text x="339.6" y="131.7">IO_L19P_T3_A10_D26_14</text>
<text x="339.6" y="126.6">IO_L18P_T2_A12_D28_14</text>
<text x="339.6" y="129.1">IO_L18N_T2_A11_D27_14</text>
<text x="392.9" y="131.7">IO_L15P_T2_DQS_34</text>
<text x="392.9" y="129.1">IO_L14N_T2_SRCC_34</text>
<text x="392.9" y="126.6">IO_L14P_T2_SRCC_34</text>
<text x="38.1" y="135.2">R810</text>
<text x="39.4" y="137">1k</text>
<text x="47.5" y="132.9">LED1</text>
<text x="47.5" y="135.5">LED2</text>
<text x="59.2" y="132.9">CLK</text>
<text x="79.2" y="132.9">IN</text>
<text x="79.2" y="136.8">GND</text>
<text x="85.6" y="136.8">NC</text>
<text x="85.6" y="132.9">NC</text>
<text x="113" y="135.2">R811</text>
<text x="114.3" y="137">1k</text>
<text x="122.4" y="132.9">LED1</text>
<text x="122.4" y="135.5">LED2</text>
<text x="134.2" y="132.9">CLK</text>
<text x="154.2" y="136.8">GND</text>
<text x="154.2" y="132.9">IN</text>
<text x="160.5" y="132.9">NC</text>
<text x="160.5" y="136.8">NC</text>
<text x="187.9" y="135.2">R812</text>
<text x="189.3" y="137">1k</text>
<text x="197.4" y="132.9">LED1</text>
<text x="197.4" y="135.5">LED2</text>
<text x="209.1" y="132.9">CLK</text>
<text x="229.1" y="132.9">NC</text>
<text x="229.1" y="136.8">NC</text>
<text x="234.2" y="136.8">GND</text>
<text x="236.1" y="132.9">IN</text>
<text x="286.3" y="134.2">IO_L15N_T2_DQS_ADV_B_15</text>
<text x="339.6" y="134.2">IO_L19N_T3_A09_D25_VREF_14</text>
<text x="392.9" y="134.2">IO_L15N_T2_DQS_34</text>
<text x="47.5" y="139.3">LED3</text>
<text x="47.5" y="141.8">LED4</text>
<text x="60.6" y="143.1">TX</text>
<text x="60.6" y="140.6">TX</text>
<text x="79.2" y="140.6">IN</text>
<text x="79.2" y="143.1">IN</text>
<text x="85.6" y="143.1">NC</text>
<text x="85.6" y="140.6">NC</text>
<text x="122.4" y="139.3">LED3</text>
<text x="122.4" y="141.8">LED4</text>
<text x="135.5" y="143.1">TX</text>
<text x="135.5" y="140.6">TX</text>
<text x="154.2" y="140.6">IN</text>
<text x="154.2" y="143.1">IN</text>
<text x="160.5" y="143.1">NC</text>
<text x="160.5" y="140.6">NC</text>
<text x="197.4" y="139.3">LED3</text>
<text x="197.4" y="141.8">LED4</text>
<text x="210.5" y="143.1">TX</text>
<text x="210.5" y="140.6">TX</text>
<text x="229.1" y="140.6">NC</text>
<text x="229.1" y="143.1">NC</text>
<text x="236.1" y="143.1">IN</text>
<text x="236.1" y="140.6">IN</text>
<text x="286.3" y="141.8">IO_L16N_T2_A27_15</text>
<text x="286.3" y="139.3">IO_L16P_T2_A28_15</text>
<text x="339.6" y="139.3">IO_L20P_T3_A08_D24_14</text>
<text x="339.6" y="141.8">IO_L20N_T3_A07_D23_14</text>
<text x="392.9" y="139.3">IO_L16P_T2_34</text>
<text x="392.9" y="141.8">IO_L16N_T2_34</text>
<text x="286.3" y="149.5">IO_L18P_T2_A24_15</text>
<text x="286.3" y="146.9">IO_L17N_T2_A25_15</text>
<text x="286.3" y="144.4">IO_L17P_T2_A26_15</text>
<text x="339.6" y="149.5">IO_L22P_T3_A05_D21_14</text>
<text x="339.6" y="144.4">IO_L21P_T3_DQS_14</text>
<text x="339.6" y="146.9">IO_L21N_T3_DQS_A06_D22_14</text>
<text x="392.9" y="149.5">IO_L18P_T2_34</text>
<text x="392.9" y="144.4">IO_L17P_T2_34</text>
<text x="392.9" y="146.9">IO_L17N_T2_34</text>
<text x="50.4" y="154.4" transform="rotate(-90 50.4 154.4)">GND</text>
<text x="54.2" y="154.4" transform="rotate(-90 54.2 154.4)">SHD</text>
<text x="58" y="154.4" transform="rotate(-90 58 154.4)">SHD</text>
<text x="60.3" y="150.7">RX</text>
<text x="60.3" y="153.3">RX</text>
<text x="79.2" y="150.7">IN</text>
<text x="79.2" y="153.3">IN</text>
<text x="85.6" y="153.3">NC</text>
<text x="85.6" y="150.7">NC</text>
<text x="125.3" y="154.4" transform="rotate(-90 125.3 154.4)">GND</text>
<text x="129.1" y="154.4" transform="rotate(-90 129.1 154.4)">SHD</text>
<text x="132.9" y="154.4" transform="rotate(-90 132.9 154.4)">SHD</text>
<text x="135.2" y="150.7">RX</text>
<text x="135.2" y="153.3">RX</text>
<text x="154.2" y="153.3">IN</text>
<text x="154.2" y="150.7">IN</text>
<text x="160.5" y="150.7">NC</text>
<text x="160.5" y="153.3">NC</text>
<text x="200.3" y="154.4" transform="rotate(-90 200.3 154.4)">GND</text>
<text x="204.1" y="154.4" transform="rotate(-90 204.1 154.4)">SHD</text>
<text x="207.9" y="154.4" transform="rotate(-90 207.9 154.4)">SHD</text>
<text x="210.2" y="150.7">RX</text>
<text x="210.2" y="153.3">RX</text>
<text x="229.1" y="153.3">IN</text>
<text x="229.1" y="150.7">IN</text>
<text x="235.4" y="150.7">NC</text>
<text x="235.4" y="153.3">NC</text>
<text x="286.3" y="152">IO_L18N_T2_A23_15</text>
<text x="339.6" y="152">IO_L22N_T3_A04_D20_14</text>
<text x="392.9" y="152">IO_L18N_T2_34</text>
<text x="79.2" y="160.9">IN</text>
<text x="79.2" y="157.1">GND</text>
<text x="85.6" y="157.1">NC</text>
<text x="85.6" y="160.9">NC</text>
<text x="154.2" y="157.1">GND</text>
<text x="154.2" y="160.9">IN</text>
<text x="160.5" y="160.9">NC</text>
<text x="160.5" y="157.1">NC</text>
<text x="229.1" y="157.1">GND</text>
<text x="229.1" y="160.9">IN</text>
<text x="235.4" y="160.9">NC</text>
<text x="235.4" y="157.1">NC</text>
<text x="286.3" y="159.6">IO_L19N_T3_A21_VREF_15</text>
<text x="286.3" y="157.1">IO_L19P_T3_A22_15</text>
<text x="339.6" y="157.1">IO_L23P_T3_A03_D19_14</text>
<text x="339.6" y="159.6">IO_L23N_T3_A02_D18_14</text>
<text x="392.9" y="159.6">IO_L19N_T3_VREF_34</text>
<text x="392.9" y="157.1">IO_L19P_T3_34</text>
<text x="51.3" y="162.4">+5V</text>
<text x="55.5" y="163.4">U819</text>
<text x="55.5" y="166">RJ45</text>
<text x="79.2" y="163.4">IN</text>
<text x="85.6" y="163.4">NC</text>
<text x="126.2" y="162.4">+5V</text>
<text x="130.4" y="163.4">U820</text>
<text x="130.4" y="166">RJ45</text>
<text x="154.2" y="163.4">IN</text>
<text x="156.2" y="167">U823</text>
<text x="160.5" y="163.4">NC</text>
<text x="201.2" y="162.4">+5V</text>
<text x="205.4" y="163.4">U821</text>
<text x="205.4" y="166">RJ45</text>
<text x="229.1" y="163.4">IN</text>
<text x="235.4" y="163.4">NC</text>
<text x="286.3" y="162.2">IO_L20P_T3_A20_15</text>
<text x="286.3" y="164.7">IO_L20N_T3_A19_15</text>
<text x="286.3" y="167.2">IO_L21P_T3_DQS_15</text>
<text x="339.6" y="162.2">IO_L24P_T3_A01_D17_14</text>
<text x="339.6" y="164.7">IO_L24N_T3_A00_D16_14</text>
<text x="392.9" y="167.2">IO_L21P_T3_DQS_34</text>
<text x="392.9" y="164.7">IO_L20N_T3_34</text>
<text x="392.9" y="162.2">IO_L20P_T3_34</text>
<text x="38.1" y="170.8">R813</text>
<text x="39.4" y="172.6">1k</text>
<text x="54.2" y="172" transform="rotate(-90 54.2 172)">VCC</text>
<text x="59.2" y="172.3">CLK</text>
<text x="79.2" y="172.3">IN</text>
<text x="85.6" y="172.3">NC</text>
<text x="113" y="170.8">R814</text>
<text x="114.3" y="172.6">1k</text>
<text x="129.1" y="172" transform="rotate(-90 129.1 172)">VCC</text>
<text x="134.2" y="172.3">CLK</text>
<text x="152.7" y="168.8">TPD4E02B04</text>
<text x="154.2" y="172.3">IN</text>
<text x="160.5" y="172.3">NC</text>
<text x="187.9" y="170.8">R815</text>
<text x="189.3" y="172.6">1k</text>
<text x="204.1" y="172" transform="rotate(-90 204.1 172)">VCC</text>
<text x="209.1" y="172.3">CLK</text>
<text x="241.8" y="172.3">IN</text>
<text x="248.1" y="172.3">NC</text>
<text x="286.3" y="169.8">IO_L21N_T3_DQS_A18_15</text>
<text x="339.6" y="172.3">IO_L6N_T0_D08_VREF_14</text>
<text x="339.6" y="169.8">IO_0_14</text>
<text x="392.9" y="169.8">IO_L21N_T3_DQS_34</text>
<text x="38.1" y="177.1">R816</text>
<text x="39.4" y="178.9">1k</text>
<text x="47.5" y="174.9">LED1</text>
<text x="47.5" y="177.4">LED2</text>
<text x="59.2" y="174.9">CLK</text>
<text x="79.2" y="174.9">IN</text>
<text x="79.2" y="178.7">GND</text>
<text x="85.6" y="178.7">NC</text>
<text x="85.6" y="174.9">NC</text>
<text x="113" y="177.1">R817</text>
<text x="114.3" y="178.9">1k</text>
<text x="122.4" y="174.9">LED1</text>
<text x="122.4" y="177.4">LED2</text>
<text x="134.2" y="174.9">CLK</text>
<text x="154.2" y="178.7">GND</text>
<text x="154.2" y="174.9">IN</text>
<text x="160.5" y="174.9">NC</text>
<text x="160.5" y="178.7">NC</text>
<text x="187.9" y="177.1">R818</text>
<text x="189.3" y="178.9">1k</text>
<text x="197.4" y="174.9">LED1</text>
<text x="197.4" y="177.4">LED2</text>
<text x="209.1" y="174.9">CLK</text>
<text x="241.8" y="178.7">GND</text>
<text x="241.8" y="174.9">IN</text>
<text x="248.1" y="174.9">NC</text>
<text x="248.1" y="178.7">NC</text>
<text x="286.3" y="177.4">IO_L22N_T3_A16_15</text>
<text x="286.3" y="174.9">IO_L22P_T3_A17_15</text>
<text x="286.3" y="179.9">IO_L23P_T3_FOE_B_15</text>
<text x="339.6" y="174.9">IO_25_14</text>
<text x="392.9" y="179.9">IO_L23P_T3_34</text>
<text x="392.9" y="177.4">IO_L22N_T3_34</text>
<text x="392.9" y="174.9">IO_L22P_T3_34</text>
<text x="47.5" y="181.2">LED3</text>
<text x="47.5" y="183.7">LED4</text>
<text x="60.6" y="185">TX</text>
<text x="60.6" y="182.5">TX</text>
<text x="79.2" y="182.5">IN</text>
<text x="79.2" y="185">IN</text>
<text x="85.6" y="185">NC</text>
<text x="85.6" y="182.5">NC</text>
<text x="122.4" y="181.2">LED3</text>
<text x="122.4" y="183.7">LED4</text>
<text x="135.5" y="185">TX</text>
<text x="135.5" y="182.5">TX</text>
<text x="154.2" y="185">IN</text>
<text x="154.2" y="182.5">IN</text>
<text x="160.5" y="182.5">NC</text>
<text x="160.5" y="185">NC</text>
<text x="197.4" y="181.2">LED3</text>
<text x="197.4" y="183.7">LED4</text>
<text x="210.5" y="185">TX</text>
<text x="210.5" y="182.5">TX</text>
<text x="241.8" y="182.5">IN</text>
<text x="241.8" y="185">IN</text>
<text x="248.1" y="185">NC</text>
<text x="248.1" y="182.5">NC</text>
<text x="286.3" y="182.5">IO_L23N_T3_FWE_B_15</text>
<text x="286.3" y="185">IO_L24P_T3_RS1_15</text>
<text x="392.9" y="185">IO_L24P_T3_34</text>
<text x="392.9" y="182.5">IO_L23N_T3_34</text>
<text x="77.7" y="188.6">TPD4E02B04</text>
<text x="81.2" y="190.3">U822</text>
<text x="286.3" y="187.6">IO_L24N_T3_RS0_15</text>
<text x="392.9" y="187.6">IO_L24N_T3_34</text>
<text x="50.4" y="196.3" transform="rotate(-90 50.4 196.3)">GND</text>
<text x="54.2" y="196.3" transform="rotate(-90 54.2 196.3)">SHD</text>
<text x="58" y="196.3" transform="rotate(-90 58 196.3)">SHD</text>
<text x="60.3" y="192.6">RX</text>
<text x="60.3" y="195.2">RX</text>
<text x="79.2" y="192.6">IN</text>
<text x="79.2" y="195.2">IN</text>
<text x="85.6" y="195.2">NC</text>
<text x="85.6" y="192.6">NC</text>
<text x="125.3" y="196.3" transform="rotate(-90 125.3 196.3)">GND</text>
<text x="129.1" y="196.3" transform="rotate(-90 129.1 196.3)">SHD</text>
<text x="132.9" y="196.3" transform="rotate(-90 132.9 196.3)">SHD</text>
<text x="135.2" y="192.6">RX</text>
<text x="135.2" y="195.2">RX</text>
<text x="154.2" y="195.2">IN</text>
<text x="154.2" y="192.6">IN</text>
<text x="160.5" y="192.6">NC</text>
<text x="160.5" y="195.2">NC</text>
<text x="200.3" y="196.3" transform="rotate(-90 200.3 196.3)">GND</text>
<text x="204.1" y="196.3" transform="rotate(-90 204.1 196.3)">SHD</text>
<text x="207.9" y="196.3" transform="rotate(-90 207.9 196.3)">SHD</text>
<text x="210.2" y="192.6">RX</text>
<text x="210.2" y="195.2">RX</text>
<text x="241.8" y="195.2">IN</text>
<text x="241.8" y="192.6">IN</text>
<text x="248.1" y="192.6">NC</text>
<text x="248.1" y="195.2">NC</text>
<text x="286.3" y="192.6">IO_0_15</text>
<text x="286.3" y="195.2">IO_25_15</text>
<text x="392.9" y="192.6">IO_0_34</text>
<text x="392.9" y="195.2">IO_25_34</text>
<text x="79.2" y="202.8">IN</text>
<text x="79.2" y="199">GND</text>
<text x="85.6" y="199">NC</text>
<text x="85.6" y="202.8">NC</text>
<text x="154.2" y="199">GND</text>
<text x="154.2" y="202.8">IN</text>
<text x="160.5" y="202.8">NC</text>
<text x="160.5" y="199">NC</text>
<text x="241.8" y="199">GND</text>
<text x="241.8" y="202.8">IN</text>
<text x="248.1" y="202.8">NC</text>
<text x="248.1" y="199">NC</text>
<text x="77.7" y="209.1">TPD4E02B04</text>
<text x="79.2" y="205.3">IN</text>
<text x="85.6" y="205.3">NC</text>
<text x="154.2" y="205.3">IN</text>
<text x="160.5" y="205.3">NC</text>
<text x="241.8" y="205.3">IN</text>
<text x="248.1" y="205.3">NC</text>
<text x="81.2" y="210.9">U825</text>
<text x="32.3" y="228.4">+5V</text>
<text x="41.1" y="228.4">+5V</text>
<text x="50" y="228.4">+5V</text>
<text x="58.9" y="228.4">+5V</text>
<text x="67.8" y="228.4">+5V</text>
<text x="76.7" y="228.4">+5V</text>
<text x="85.6" y="228.4">+5V</text>
<text x="94.5" y="228.4">+5V</text>
<text x="103.4" y="228.4">+5V</text>
<text x="133.4" y="232">H801</text>
<text x="141" y="232">H802</text>
<text x="148.6" y="232">H803</text>
<text x="156.2" y="232">H804</text>
<text x="27.1" y="234.5">D801</text>
<text x="28.8" y="237.1">TVS</text>
<text x="36" y="234.5">D802</text>
<text x="37.7" y="237.1">TVS</text>
<text x="44.9" y="234.5">D803</text>
<text x="46.6" y="237.1">TVS</text>
<text x="53.8" y="234.5">D804</text>
<text x="55.4" y="237.1">TVS</text>
<text x="62.7" y="234.5">D805</text>
<text x="64.3" y="237.1">TVS</text>
<text x="71.6" y="234.5">D806</text>
<text x="73.2" y="237.1">TVS</text>
<text x="80.5" y="234.5">D807</text>
<text x="82.1" y="237.1">TVS</text>
<text x="89.4" y="234.5">D808</text>
<text x="91" y="237.1">TVS</text>
<text x="98.3" y="234.5">D809</text>
<text x="99.9" y="237.1">TVS</text>
<text x="133.4" y="234.5">M3</text>
<text x="141" y="234.5">M3</text>
<text x="148.6" y="234.5">M3</text>
<text x="156.2" y="234.5">M3</text>
</g>
<g font-size="1.3" fill="#0f0f0f">
<text x="325.1" y="49.2">P2_TX_P</text>
<text x="325.1" y="51.7">P2_TX_N</text>
<text x="325.1" y="59.3">P3_CLK_P R18</text>
<text x="378.5" y="59.3">P1_TX_P</text>
<text x="325.1" y="61.9">P3_CLK_N</text>
<text x="378.5" y="61.9">P1_TX_N</text>
<text x="325.1" y="74.6">P3_RX_N</text>
<text x="325.1" y="72">P3_RX_P</text>
<text x="66.7" y="83.5">P1_CLK_P 5</text>
<text x="92.1" y="83.5">P1_CLK_P</text>
<text x="141.7" y="83.5">P4_CLK_P 5</text>
<text x="167.1" y="83.5">P4_CLK_P</text>
<text x="216.6" y="83.5">P7_CLK_P 5</text>
<text x="242" y="83.5">P7_CLK_P</text>
<text x="66.7" y="86">P1_CLK_N 4</text>
<text x="92.1" y="86">P1_CLK_N</text>
<text x="141.6" y="86">P4_CLK_N 4</text>
<text x="167" y="86">P4_CLK_N</text>
<text x="216.5" y="86">P7_CLK_N 4</text>
<text x="241.9" y="86">P7_CLK_N</text>
<text x="378.5" y="84.7">P1_RX_P</text>
<text x="378.5" y="87.3">P1_RX_N</text>
<text x="66.8" y="93.6">P1_TX_P</text>
<text x="93.5" y="93.6">P1_TX_P</text>
<text x="141.8" y="93.6">P4_TX_P</text>
<text x="168.4" y="93.6">P4_TX_P</text>
<text x="216.7" y="93.6">P7_TX_P</text>
<text x="243.4" y="93.6">P7_TX_P</text>
<text x="378.5" y="94.9">P6_TX_P</text>
<text x="66.8" y="96.2">P1_TX_N</text>
<text x="93.5" y="96.2">P1_TX_N</text>
<text x="141.7" y="96.2">P4_TX_N</text>
<text x="168.4" y="96.2">P4_TX_N</text>
<text x="216.6" y="96.2">P7_TX_N</text>
<text x="243.3" y="96.2">P7_TX_N</text>
<text x="378.5" y="97.4">P6_TX_N</text>
<text x="66.5" y="106.3">P1_RX_N</text>
<text x="66.5" y="103.8">P1_RX_P</text>
<text x="93.2" y="106.3">P1_RX_N</text>
<text x="93.2" y="103.8">P1_RX_P</text>
<text x="141.4" y="106.3">P4_RX_N</text>
<text x="141.5" y="103.8">P4_RX_P</text>
<text x="168.1" y="106.3">P4_RX_N</text>
<text x="168.1" y="103.8">P4_RX_P</text>
<text x="216.3" y="106.3">P7_RX_N</text>
<text x="216.4" y="103.8">P7_RX_P</text>
<text x="243" y="106.3">P7_RX_N</text>
<text x="243.1" y="103.8">P7_RX_P</text>
<text x="271.8" y="105.1">P9_RX_N</text>
<text x="271.8" y="102.5">P9_RX_P</text>
<text x="378.5" y="105.1">P6_CLK_N</text>
<text x="378.5" y="102.5">P6_CLK_P</text>
<text x="325.1" y="112.7">P5_CLK_P</text>
<text x="325.1" y="115.2">P5_CLK_N</text>
<text x="325.1" y="122.8">P3_TX_N</text>
<text x="325.1" y="120.3">P3_TX_P</text>
<text x="325.1" y="125.4">P5_RX_P</text>
<text x="66.7" y="131.7">P2_CLK_N 2</text>
<text x="66.7" y="129.2">P2_CLK_P 1</text>
<text x="92.1" y="131.7">P2_CLK_N</text>
<text x="141.4" y="131.7">P5_CLK_N</text>
<text x="141.5" y="129.2">P5_CLK_P</text>
<text x="167" y="131.7">P5_CLK_N</text>
<text x="167.1" y="129.2">P5_CLK_P</text>
<text x="216.5" y="131.7">P8_CLK_N 7</text>
<text x="216.6" y="129.2">P8_CLK_P 6</text>
<text x="241.9" y="131.7">P8_CLK_N</text>
<text x="242" y="129.2">P8_CLK_P</text>
<text x="325.1" y="127.9">P5_RX_N</text>
<text x="325.1" y="130.5">P4_CLK_P</text>
<text x="378.5" y="130.5">P1_CLK_P</text>
<text x="325.1" y="133">P4_CLK_N U11</text>
<text x="378.5" y="133">P1_CLK_N</text>
<text x="66.8" y="141.9">P2_TX_N</text>
<text x="66.8" y="139.4">P2_TX_P</text>
<text x="93.5" y="141.9">P2_TX_N</text>
<text x="93.5" y="139.4">P2_TX_P</text>
<text x="141.5" y="141.9">P5_TX_N</text>
<text x="141.6" y="139.4">P5_TX_P</text>
<text x="168.4" y="141.9">P5_TX_N</text>
<text x="168.4" y="139.4">P5_TX_P</text>
<text x="216.6" y="141.9">P8_TX_N</text>
<text x="216.7" y="139.4">P8_TX_P</text>
<text x="243.3" y="141.9">P8_TX_N</text>
<text x="243.4" y="139.4">P8_TX_P</text>
<text x="325.1" y="138.1">P4_RX_P</text>
<text x="325.1" y="140.6">P4_RX_N</text>
<text x="66.5" y="149.5">P2_RX_P</text>
<text x="93.2" y="149.5">P2_RX_P</text>
<text x="141.3" y="149.5">P5_RX_P</text>
<text x="168.1" y="149.5">P5_RX_P</text>
<text x="216.4" y="149.5">P8_RX_P</text>
<text x="243.1" y="149.5">P8_RX_P</text>
<text x="271.8" y="148.2">P2_RX_P</text>
<text x="325.1" y="148.2">P5_TX_P</text>
<text x="66.5" y="152.1">P2_RX_N</text>
<text x="93.2" y="152.1">P2_RX_N</text>
<text x="141.2" y="152.1">P5_RX_N</text>
<text x="168.1" y="152.1">P5_RX_N</text>
<text x="216.3" y="152.1">P8_RX_N</text>
<text x="243" y="152.1">P8_RX_N</text>
<text x="271.8" y="150.8">P2_RX_N</text>
<text x="325.1" y="150.8">P5_TX_N</text>
<text x="271.8" y="160.9">P9_CLK_P C16</text>
<text x="378.5" y="160.9">P6_RX_P</text>
<text x="271.8" y="163.5">P9_CLK_N C17</text>
<text x="271.8" y="166">P9_TX_P</text>
<text x="378.5" y="163.5">P6_RX_N</text>
<text x="378.5" y="166">P4_TX_P</text>
<text x="66.7" y="173.6">P3_CLK_N 2</text>
<text x="66.7" y="171.1">P3_CLK_P 1</text>
<text x="92.1" y="173.6">P3_CLK_N</text>
<text x="141.6" y="173.6">P6_CLK_N 4</text>
<text x="141.7" y="171.1">P6_CLK_P 5</text>
<text x="167" y="173.6">P6_CLK_N</text>
<text x="167.1" y="171.1">P6_CLK_P</text>
<text x="216.5" y="173.6">P9_CLK_N</text>
<text x="216.6" y="171.1">P9_CLK_P</text>
<text x="254.6" y="173.6">P9_CLK_N</text>
<text x="254.7" y="171.1">P9_CLK_P</text>
<text x="271.8" y="168.6">P9_TX_N</text>
<text x="378.5" y="168.6">P4_TX_N</text>
<text x="271.8" y="178.7">P2_CLK_P</text>
<text x="66.8" y="183.8">P3_TX_N</text>
<text x="66.8" y="181.3">P3_TX_P</text>
<text x="93.5" y="183.8">P3_TX_N</text>
<text x="93.5" y="181.3">P3_TX_P</text>
<text x="141.7" y="183.8">P6_TX_N</text>
<text x="141.8" y="181.3">P6_TX_P</text>
<text x="168.4" y="183.8">P6_TX_N</text>
<text x="168.4" y="181.3">P6_TX_P</text>
<text x="216.6" y="183.8">P9_TX_N</text>
<text x="216.7" y="181.3">P9_TX_P</text>
<text x="228.6" y="183.8">P9_RX_N</text>
<text x="228.6" y="181.3">P9_RX_P</text>
<text x="255.7" y="183.8">P9_RX_N</text>
<text x="255.8" y="181.3">P9_RX_P</text>
<text x="271.8" y="181.3">P2_CLK_N</text>
<text x="66.5" y="191.4">P3_RX_P</text>
<text x="93.2" y="191.4">P3_RX_P</text>
<text x="141.5" y="191.4">P6_RX_P</text>
<text x="168.1" y="191.4">P6_RX_P</text>
<text x="216.4" y="191.4">P9_RX_P</text>
<text x="228.6" y="191.4">P9_TX_P</text>
<text x="256.1" y="191.4">P9_TX_P</text>
<text x="66.5" y="194">P3_RX_N</text>
<text x="93.2" y="194">P3_RX_N</text>
<text x="141.4" y="194">P6_RX_N</text>
<text x="168.1" y="194">P6_RX_N</text>
<text x="216.3" y="194">P9_RX_N</text>
<text x="228.6" y="194">P9_TX_N</text>
<text x="256" y="194">P9_TX_N</text>
</g>
</g></defs>
<g fill="none" stroke="#840000" stroke-width=".18">
<path d="M10 10h400v277h-400zM12 12h396v273h-396zM60 10v2M110 10v2M160 10v2M210 10v2M260 10v2M310 10v2M360 10v2M10 60h2M408 60h2M186.7 92.7h1.3"/>
<path d="M186.7 86.4h1.3M193 92.7h1.3M193 86.4h1.3M194.3 88.9v1.3h-1.3l1.3 1.2 1.3-1.2h-1.3M194.3 88.9h.1M194.3 95.3v1.2h-1.3l1.3 1.3 1.3-1.3h-1.3M194.3 95.3h.1M10 110h2M128.3 111.8v1.2h-1.3l1.3 1.3 1.2-1.3h-1.2M128.3 111.8h.1M132.1 111.8v1.2h-1.3l1.3 1.3 1.2-1.3h-1.2M132.1 111.8h.1"/>
<path d="M408 110h2M36.8 138.4h1.3M36.8 132.1h1.3M43.2 138.4h1.2M43.2 132.1h1.2M44.4 134.6v1.3h-1.2l1.2 1.3 1.3-1.3h-1.3M44.4 134.6h.1M76.2 135.9v1.3h-1.3l1.3 1.2 1.3-1.2h-1.3M76.2 135.9h.1M10 160h2M207 157.5v1.3h-1.3l1.3 1.2 1.3-1.2h-1.3M207 157.5h.1"/>
<path d="M408 160h2M10 210h2M408 210h2M300 253h108v32h-108zM10 260h2M300 278.5h108M300 274.5h108M300 268.5h108M320 278.5v3M384 278.5v6.5M408 260h2M60 285v2"/>
<path d="M110 285v2M160 285v2M210 285v2M260 285v2M300 281.5h108M310 285v2M360 285v2"/>
</g>
<path d="M188 91.7h5v2h-5zM188 85.3h5v2.1h-5zM38.1 137.4h5.1v2h-5.1zM38.1 131.1h5.1v2h-5.1z" fill="none" stroke="#840000" stroke-width=".25"/>
<path d="M196.8 80h16.6v29.2h-16.6z" fill="#00c200"/>
<g fill="none" stroke="#840000" stroke-width=".18">
<path d="M203.2 77.5v2.5M194.3 86.4h2.5M194.3 88.9h2.5M194.3 92.7h2.5M194.3 95.3h2.5M196.8 80h16.6v29.2h-16.6zM198.8 98.4h8.2v5.7h-8.2zM200.9 98.4v.7M202.2 98.4v.7M202.6 87h1.2l-.6 .6zM202.6 93.6h1.2l-.6 .6zM202.6 87.6h1.2"/>
<path d="M202.6 94.2h1.2M203.2 86.4v.6M203.2 87.6v.7M203.2 93v.6M203.2 94.2v.7M203.5 98.4v.7M204.7 98.4v.7M210.3 82l.5 .4 .5-.4M210.3 82.3l.5-.3 .5 .3M210.6 92.1l.5 .3 .5-.3M210.6 92.3l.5-.3 .5 .3M211.1 82l.5 .4 .5-.4"/>
<path d="M211.1 82.3l.5-.3 .5 .3M211.3 92.1l.5 .3 .5-.3M211.3 92.3l.5-.3 .5 .3M213.4 83.8h2.5M213.4 86.4h2.5M213.4 96.5h2.5M213.4 94h2.5M198.8 102.2h1.9v1.3h4.4v-1.3h1.9M199.4 109.2v2.6M203.2 109.2v2.6M207 109.2v2.6M210.3 102.2l.5 .4 .5-.4"/>
<path d="M210.3 102.5l.5-.3 .5 .3M211.1 102.2l.5 .4 .5-.4M211.1 102.5l.5-.3 .5 .3M213.4 104.1h2.5M213.4 106.7h2.5M241.3 135.9v1.3h-1.3l1.3 1.2 1.3-1.2h-1.3M241.3 135.9h.1"/>
</g>
<path d="M209.2 85.3h3.5M210.6 95.4h2.1M210.3 105.6h2.4" fill="none" stroke="#006464" stroke-width=".18"/>
<path d="M228.6 127h10.2v17.8h-10.2z" fill="#ffffc2"/>
<g fill="none" stroke="#840000" stroke-width=".18">
<path d="M226.1 110.5v1.3h-1.3l1.3 1.2 1.2-1.2h-1.2M226.1 110.5h.1M241.3 110.5v1.3h-1.3l1.3 1.2 1.3-1.2h-1.3M241.3 110.5h.1M128.3 123.2h.1M128.3 120.7l-.8 1.2M128.3 120.7l.7 1.2M128.3 120.7v2.5M226.1 135.9v1.3h-1.3l1.3 1.2 1.2-1.2h-1.2M226.1 135.9h.1M226.1 139.7h2.5M226.1 135.9h2.5"/>
<path d="M226.1 132.1h2.5M226.1 129.5h2.5M228.6 127h10.2v17.8h-10.2zM238.8 139.7h2.5M238.8 135.9h2.5M238.8 132.1h2.5M238.8 129.5h2.5M226.1 156.2v1.3h-1.3l1.3 1.3 1.2-1.3h-1.2M226.1 156.2h.1M226.1 142.2h2.5M238.8 142.2h2.5"/>
</g>
<path d="M47 125.7h16.5v29.2h-16.5z" fill="#00c200"/>
<g fill="none" stroke="#840000" stroke-width=".18">
<path d="M44.4 132.1h2.6M44.4 134.6h2.6M44.4 138.4h2.6M47 125.7h16.5v29.2h-16.5zM52.7 132.7h1.3l-.7 .7zM52.7 139.3h1.3l-.7 .7zM52.7 133.4h1.3M52.7 140h1.3M53.3 123.2v2.5M53.3 132.1v.6M53.3 133.4v.6M53.3 138.7v.6"/>
<path d="M53.3 140v.6M60.5 127.8l.5 .3 .5-.3M60.5 128l.5-.3 .5 .3M60.7 137.8l.5 .3 .5-.3M60.7 138l.5-.3 .5 .3M61.2 127.8l.5 .3 .5-.3M61.2 128l.5-.3 .5 .3M61.5 137.8l.5 .3 .5-.3M61.5 138l.5-.3 .5 .3M63.5 129.5h2.5M63.5 132.1h2.5M63.5 139.7h2.5"/>
<path d="M44.4 141h2.6M48.9 144.1h8.2v5.8h-8.2zM48.9 148h1.9v1.2h4.4v-1.2h1.9M49.5 154.9v2.6M51.1 144.1v.7M52.3 144.1v.7M53.3 154.9v2.6M53.6 144.1v.7M54.9 144.1v.7M57.1 154.9v2.6M60.5 148l.5 .3 .5-.3M60.5 148.2l.5-.3 .5 .3"/>
<path d="M61.2 148l.5 .3 .5-.3M61.2 148.2l.5-.3 .5 .3M63.5 149.9h2.5M63.5 152.4h2.5M63.5 142.2h2.5"/>
</g>
<path d="M59.3 131h3.6M60.4 151.3h2.5M60.7 141.1h2.2" fill="none" stroke="#006464" stroke-width=".18"/>
<path d="M78.7 147.3h10.2v17.8h-10.2z" fill="#ffffc2"/>
<path d="M76.2 156.2h2.5M76.2 149.9h2.5M76.2 152.4h2.5M78.7 147.3h10.2v17.8h-10.2zM88.9 156.2h2.5M88.9 149.9h2.5M88.9 152.4h2.5M76.2 162.6h2.5M76.2 160h2.5M88.9 162.6h2.5M88.9 160h2.5" fill="none" stroke="#840000" stroke-width=".18"/>
<path d="M78.7 127h10.2v17.8h-10.2z" fill="#ffffc2"/>
<g fill="none" stroke="#840000" stroke-width=".18">
<path d="M53.3 123.2h.1M53.3 120.7l-.7 1.2M53.3 120.7l.8 1.2M53.3 120.7v2.5M76.2 129.5h2.5M76.2 132.1h2.5M76.2 135.9h2.5M76.2 139.7h2.5M78.7 127h10.2v17.8h-10.2zM88.9 129.5h2.5M88.9 132.1h2.5M88.9 135.9h2.5"/>
<path d="M88.9 139.7h2.5M76.2 142.2h2.5M88.9 142.2h2.5"/>
</g>
<path d="M196.8 125.7h16.6v29.2h-16.6z" fill="#00c200"/>
<g fill="none" stroke="#840000" stroke-width=".18">
<path d="M203.2 77.5h.1M203.2 74.9v2.6M203.2 74.9l-.8 1.3M203.2 74.9l.8 1.3M49.5 111.8v1.2h-1.2l1.2 1.3 1.3-1.3h-1.3M49.5 111.8h.1M57.1 111.8v1.2h-1.2l1.2 1.3 1.3-1.3h-1.3M57.1 111.8h.1M124.5 111.8v1.2h-1.3l1.3 1.3 1.2-1.3h-1.2M124.5 111.8h.1M194.3 132.1h2.5M194.3 134.6h2.5"/>
<path d="M194.3 138.4h2.5M196.8 125.7h16.6v29.2h-16.6zM202.6 132.7h1.2l-.6 .7zM202.6 139.3h1.2l-.6 .7zM202.6 133.4h1.2M202.6 140h1.2M203.2 123.2v2.5M203.2 132.1v.6M203.2 133.4v.6M203.2 138.7v.6M203.2 140v.6M210.3 127.8l.5 .3 .5-.3"/>
<path d="M210.3 128l.5-.3 .5 .3M210.6 137.8l.5 .3 .5-.3M210.6 138l.5-.3 .5 .3M211.1 127.8l.5 .3 .5-.3M211.1 128l.5-.3 .5 .3M211.3 137.8l.5 .3 .5-.3M211.3 138l.5-.3 .5 .3M213.4 129.5h2.5M213.4 132.1h2.5M213.4 139.7h2.5M194.3 141h2.5M198.8 144.1h8.2v5.8h-8.2z"/>
<path d="M198.8 148h1.9v1.2h4.4v-1.2h1.9M199.4 154.9v2.6M200.9 144.1v.7M202.2 144.1v.7M203.2 154.9v2.6M203.5 144.1v.7M204.7 144.1v.7M207 154.9v2.6M210.3 148l.5 .3 .5-.3M210.3 148.2l.5-.3 .5 .3M211.1 148l.5 .3 .5-.3M211.1 148.2l.5-.3 .5 .3"/>
<path d="M213.4 149.9h2.5M213.4 152.4h2.5M213.4 142.2h2.5"/>
</g>
<path d="M209.2 131h3.5M210.3 151.3h2.4M210.6 141.1h2.1" fill="none" stroke="#006464" stroke-width=".18"/>
<path d="M392.4 39.4h27.6v158.7h-27.6z" fill="#ffffc2"/>
<g fill="none" stroke="#840000" stroke-width=".18">
<path d="M420 39.4h-27.6v158.7h27.6M388.6 54.6h3.8M388.6 49.5h3.8M388.6 57.2h3.8M388.6 52.1h3.8M388.6 59.7h3.8M388.6 72.4h3.8M388.6 74.9h3.8M388.6 77.5h3.8M388.6 69.9h3.8M388.6 67.3h3.8M388.6 62.2h3.8"/>
<path d="M36.8 92.7h1.3M43.2 92.7h1.2M44.4 88.9v1.3h-1.2l1.2 1.2 1.3-1.2h-1.3M44.4 88.9h.1M44.4 95.3v1.2h-1.2l1.2 1.3 1.3-1.3h-1.3M44.4 95.3h.1M388.6 80h3.8M388.6 85.1h3.8M388.6 95.3h3.8M388.6 92.7h3.8M388.6 90.2h3.8M388.6 87.6h3.8"/>
<path d="M388.6 97.8h3.8M53.3 111.8v1.2h-1.2l1.2 1.3 1.3-1.3h-1.3M53.3 111.8h.1M388.6 108h3.8M388.6 110.5h3.8M388.6 115.6h3.8M388.6 113h3.8M388.6 105.4h3.8M388.6 102.9h3.8M111.8 132.1h1.2M118.1 132.1h1.3M388.6 138.4h3.8"/>
<path d="M388.6 120.7h3.8M388.6 130.8h3.8M388.6 128.3h3.8M388.6 125.7h3.8M388.6 123.2h3.8M388.6 133.4h3.8M241.3 156.2v1.3h-1.3l1.3 1.3 1.3-1.3h-1.3M241.3 156.2h.1M388.6 148.6h3.8M388.6 141h3.8M388.6 151.1h3.8M388.6 143.5h3.8"/>
<path d="M388.6 158.8h3.8M388.6 156.2h3.8M388.6 146.1h3.8M388.6 179.1h3.8M388.6 176.5h3.8M388.6 174h3.8M388.6 166.4h3.8M388.6 163.8h3.8M388.6 161.3h3.8M388.6 168.9h3.8M199.4 199.4v1.3h-1.3l1.3 1.2 1.3-1.2h-1.3M199.4 199.4h.1"/>
<path d="M238.8 198.1v1.3h-1.3l1.3 1.3 1.2-1.3h-1.2M238.8 198.1h.1M388.6 191.8h3.8M388.6 184.2h3.8M388.6 181.6h3.8M388.6 186.7h3.8M388.6 194.3h3.8"/>
</g>
<path d="M38.1 91.7h5.1v2h-5.1zM113 131.1h5.1v2h-5.1z" fill="none" stroke="#840000" stroke-width=".25"/>
<path d="M228.6 147.3h10.2v17.8h-10.2z" fill="#ffffc2"/>
<g fill="none" stroke="#840000" stroke-width=".18">
<path d="M76.2 90.2v1.2h-1.3l1.3 1.3 1.3-1.3h-1.3M76.2 90.2h.1M226.1 152.4h2.5M226.1 149.9h2.5M226.1 156.2h2.5M228.6 147.3h10.2v17.8h-10.2zM238.8 152.4h2.5M238.8 149.9h2.5M238.8 156.2h2.5M226.1 160h2.5M226.1 162.6h2.5M238.8 160h2.5"/>
<path d="M238.8 162.6h2.5"/>
</g>
<path d="M78.7 101.6h10.2v17.8h-10.2z" fill="#ffffc2"/>
<g fill="none" stroke="#840000" stroke-width=".18">
<path d="M76.2 110.5v1.3h-1.3l1.3 1.2 1.3-1.2h-1.3M76.2 110.5h.1M76.2 106.7h2.5M76.2 104.1h2.5M76.2 110.5h2.5M76.2 116.8h2.5M76.2 114.3h2.5M78.7 101.6h10.2v17.8h-10.2zM88.9 106.7h2.5M88.9 104.1h2.5M88.9 110.5h2.5M88.9 116.8h2.5"/>
<path d="M88.9 114.3h2.5"/>
</g>
<path d="M78.7 81.3h10.2v17.8h-10.2z" fill="#ffffc2"/>
<g fill="none" stroke="#840000" stroke-width=".18">
<path d="M76.2 96.5h2.5M76.2 94h2.5M76.2 90.2h2.5M76.2 86.4h2.5M76.2 83.8h2.5M78.7 81.3h10.2v17.8h-10.2zM88.9 96.5h2.5M88.9 94h2.5M88.9 90.2h2.5M88.9 86.4h2.5M88.9 83.8h2.5M203.2 199.4v1.3h-1.3l1.3 1.2 1.3-1.2h-1.3"/>
<path d="M203.2 199.4h.1"/>
</g>
<path d="M241.3 168.9h10.2v17.8h-10.2z" fill="#ffffc2"/>
<g fill="none" stroke="#840000" stroke-width=".18">
<path d="M36.8 86.4h1.3M43.2 86.4h1.2M91.4 90.2v1.2h-1.2l1.2 1.3 1.3-1.3h-1.3M91.4 90.2h.1M111.8 92.7h1.2M111.8 86.4h1.2M118.1 92.7h1.3M118.1 86.4h1.3M226.1 90.2v1.2h-1.3l1.3 1.3 1.2-1.3h-1.2M226.1 90.2h.1M241.3 90.2v1.2h-1.3l1.3 1.3 1.3-1.3h-1.3M241.3 90.2h.1"/>
<path d="M91.4 110.5v1.3h-1.2l1.2 1.2 1.3-1.2h-1.3M91.4 110.5h.1M91.4 135.9v1.3h-1.2l1.2 1.2 1.3-1.2h-1.3M91.4 135.9h.1M111.8 138.4h1.2M118.1 138.4h1.3M49.5 157.5v1.3h-1.2l1.2 1.2 1.3-1.2h-1.3M49.5 157.5h.1M53.3 157.5v1.3h-1.2l1.2 1.2 1.3-1.2h-1.3M53.3 157.5h.1M57.1 157.5v1.3h-1.2l1.2 1.2 1.3-1.2h-1.3M57.1 157.5h.1"/>
<path d="M76.2 156.2v1.3h-1.3l1.3 1.3 1.3-1.3h-1.3M76.2 156.2h.1M53.3 165.1h.1M53.3 162.6l-.7 1.2M53.3 162.6l.8 1.2M53.3 162.6v2.5M238.8 177.8h2.5M238.8 171.5h2.5M238.8 174h2.5M241.3 168.9h10.2v17.8h-10.2zM251.5 177.8h2.5M251.5 171.5h2.5"/>
<path d="M251.5 174h2.5M238.8 181.6h2.5M238.8 184.2h2.5M251.5 181.6h2.5M251.5 184.2h2.5"/>
</g>
<path d="M38.1 85.3h5.1v2.1h-5.1zM113 91.7h5.1v2h-5.1zM113 85.3h5.1v2.1h-5.1zM113 137.4h5.1v2h-5.1z" fill="none" stroke="#840000" stroke-width=".25"/>
<path d="M228.6 81.3h10.2v17.8h-10.2z" fill="#ffffc2"/>
<g fill="none" stroke="#840000" stroke-width=".18">
<path d="M53.3 77.5h.1M53.3 74.9l-.7 1.3M53.3 74.9l.8 1.3M53.3 74.9v2.6M128.3 77.5h.1M128.3 74.9l-.8 1.3M128.3 74.9l.7 1.3M128.3 74.9v2.6M119.4 95.3v1.2h-1.3l1.3 1.3 1.2-1.3h-1.2M119.4 95.3h.1M119.4 88.9v1.3h-1.3l1.3 1.2 1.2-1.2h-1.2M119.4 88.9h.1"/>
<path d="M226.1 96.5h2.5M226.1 94h2.5M226.1 90.2h2.5M226.1 86.4h2.5M226.1 83.8h2.5M228.6 81.3h10.2v17.8h-10.2zM238.8 96.5h2.5M238.8 94h2.5M238.8 90.2h2.5M238.8 86.4h2.5M238.8 83.8h2.5M199.4 157.5v1.3h-1.3l1.3 1.2 1.3-1.2h-1.3"/>
<path d="M199.4 157.5h.1M203.2 157.5v1.3h-1.3l1.3 1.2 1.3-1.2h-1.3M203.2 157.5h.1M238.8 177.8v1.3h-1.3l1.3 1.2 1.2-1.2h-1.2M238.8 177.8h.1M254 177.8v1.3h-1.3l1.3 1.2 1.3-1.2h-1.3M254 177.8h.1"/>
</g>
<path d="M228.6 101.6h10.2v17.8h-10.2z" fill="#ffffc2"/>
<g fill="none" stroke="#840000" stroke-width=".18">
<path d="M226.1 106.7h2.5M226.1 104.1h2.5M226.1 110.5h2.5M226.1 114.3h2.5M226.1 116.8h2.5M228.6 101.6h10.2v17.8h-10.2zM238.8 106.7h2.5M238.8 104.1h2.5M238.8 110.5h2.5M238.8 114.3h2.5M238.8 116.8h2.5M119.4 182.9v1.3h-1.3l1.3 1.2 1.2-1.2h-1.2"/>
<path d="M119.4 182.9h.1M124.5 199.4v1.3h-1.3l1.3 1.2 1.2-1.2h-1.2M124.5 199.4h.1M128.3 199.4v1.3h-1.3l1.3 1.2 1.2-1.2h-1.2M128.3 199.4h.1M132.1 199.4v1.3h-1.3l1.3 1.2 1.2-1.2h-1.2M132.1 199.4h.1"/>
</g>
<path d="M121.9 167.6h16.5v29.3h-16.5z" fill="#00c200"/>
<g fill="none" stroke="#840000" stroke-width=".18">
<path d="M186.7 138.4h1.3M193 138.4h1.3M44.4 176.5v1.3h-1.2l1.2 1.3 1.3-1.3h-1.3M44.4 176.5h.1M76.2 177.8v1.3h-1.3l1.3 1.2 1.3-1.2h-1.3M76.2 177.8h.1M119.4 174h2.5M119.4 176.5h2.5M121.9 167.6h16.5v29.3h-16.5zM127.6 174.6h1.3l-.6 .7zM127.6 175.3h1.3M128.3 165.1v2.5"/>
<path d="M128.3 174v.6M128.3 175.3v.6M135.4 169.7l.5 .3 .5-.3M135.4 169.9l.5-.3 .5 .3M135.6 179.7l.5 .3 .6-.3M135.6 180l.5-.4 .6 .4M136.1 169.7l.6 .3 .5-.3M136.1 169.9l.6-.3 .5 .3M136.4 179.7l.5 .3 .5-.3M136.4 180l.5-.4 .5 .4M138.4 171.5h2.6M138.4 174h2.6"/>
<path d="M76.2 198.1v1.3h-1.3l1.3 1.3 1.3-1.3h-1.3M76.2 198.1h.1M91.4 198.1v1.3h-1.2l1.2 1.3 1.3-1.3h-1.3M91.4 198.1h.1M119.4 180.3h2.5M119.4 182.9h2.5M123.8 186.1h8.3v5.7h-8.3zM123.8 189.9h1.9v1.2h4.5v-1.2h1.9M124.5 196.9v2.5M126 186.1v.6M127.3 186.1v.6M127.6 181.2h1.3l-.6 .7z"/>
<path d="M127.6 181.9h1.3M128.3 180.6v.6M128.3 181.9v.6M128.3 196.9v2.5M128.5 186.1v.6M129.8 186.1v.6M132.1 196.9v2.5M135.4 189.9l.5 .3 .5-.3M135.4 190.1l.5-.3 .5 .3M136.1 189.9l.6 .3 .5-.3M136.1 190.1l.6-.3 .5 .3M138.4 191.8h2.6"/>
<path d="M138.4 194.3h2.6M138.4 184.2h2.6M138.4 181.6h2.6M151.1 198.1v1.3h-1.2l1.2 1.3 1.3-1.3h-1.3M151.1 198.1h.1M130.8 236.2v1.3h-1.3l1.3 1.3 1.3-1.3h-1.3M130.8 236.2h.1M130.8 233.7v2.5M138.4 236.2v1.3h-1.2l1.2 1.3 1.3-1.3h-1.3M138.4 236.2h.1M138.4 233.7v2.5M146 236.2v1.3h-1.2l1.2 1.3 1.3-1.3h-1.3"/>
<path d="M146 236.2h.1M146 233.7v2.5M153.7 236.2v1.3h-1.3l1.3 1.3 1.2-1.3h-1.2M153.7 236.2h.1M153.7 233.7v2.5"/>
</g>
<path d="M134.3 172.9h3.5M135.4 193.2h2.4M135.7 183h2.1" fill="none" stroke="#006464" stroke-width=".18"/>
<g fill="none" stroke="#840000" stroke-width="1.3">
<circle cx="130.8" cy="232.4" r="1.27"/>
<circle cx="138.4" cy="232.4" r="1.27"/>
<circle cx="146" cy="232.4" r="1.27"/>
<circle cx="153.7" cy="232.4" r="1.27"/>
</g>
<path d="M188 137.4h5v2h-5z" fill="none" stroke="#840000" stroke-width=".25"/>
<path d="M78.7 189.2h10.2v17.8h-10.2z" fill="#ffffc2"/>
<g fill="none" stroke="#840000" stroke-width=".18">
<path d="M194.3 134.6v1.3h-1.3l1.3 1.3 1.3-1.3h-1.3M194.3 134.6h.1M76.2 198.1h2.5M76.2 191.8h2.5M76.2 194.3h2.5M78.7 189.2h10.2v17.8h-10.2zM88.9 198.1h2.5M88.9 191.8h2.5M88.9 194.3h2.5M76.2 201.9h2.5M76.2 204.5h2.5M88.9 201.9h2.5"/>
<path d="M88.9 204.5h2.5"/>
</g>
<path d="M121.9 80h16.5v29.2h-16.5z" fill="#00c200"/>
<g fill="none" stroke="#840000" stroke-width=".18">
<path d="M128.3 77.5v2.5M119.4 86.4h2.5M119.4 88.9h2.5M119.4 92.7h2.5M119.4 95.3h2.5M121.9 80h16.5v29.2h-16.5zM123.8 98.4h8.3v5.7h-8.3zM126 98.4v.7M127.3 98.4v.7M127.6 87h1.3l-.6 .6zM127.6 93.6h1.3l-.6 .6zM127.6 87.6h1.3"/>
<path d="M127.6 94.2h1.3M128.3 86.4v.6M128.3 87.6v.7M128.3 93v.6M128.3 94.2v.7M128.5 98.4v.7M129.8 98.4v.7M135.4 82l.5 .4 .5-.4M135.4 82.3l.5-.3 .5 .3M135.6 92.1l.5 .3 .6-.3M135.6 92.3l.5-.3 .6 .3M136.1 82l.6 .4 .5-.4"/>
<path d="M136.1 82.3l.6-.3 .5 .3M136.4 92.1l.5 .3 .5-.3M136.4 92.3l.5-.3 .5 .3M138.4 83.8h2.6M138.4 86.4h2.6M138.4 96.5h2.6M138.4 94h2.6M123.8 102.2h1.9v1.3h4.5v-1.3h1.9M124.5 109.2v2.6M128.3 109.2v2.6M132.1 109.2v2.6M135.4 102.2l.5 .4 .5-.4"/>
<path d="M135.4 102.5l.5-.3 .5 .3M136.1 102.2l.6 .4 .5-.4M136.1 102.5l.6-.3 .5 .3M138.4 104.1h2.6M138.4 106.7h2.6"/>
</g>
<path d="M134.3 85.3h3.5M135.7 95.4h2.1M135.4 105.6h2.4" fill="none" stroke="#006464" stroke-width=".18"/>
<path d="M47 80h16.5v29.2h-16.5z" fill="#00c200"/>
<g fill="none" stroke="#840000" stroke-width=".18">
<path d="M53.3 77.5v2.5M44.4 86.4h2.6M44.4 88.9h2.6M44.4 92.7h2.6M44.4 95.3h2.6M47 80h16.5v29.2h-16.5zM48.9 98.4h8.2v5.7h-8.2zM51.1 98.4v.7M52.3 98.4v.7M52.7 87h1.3l-.7 .6zM52.7 93.6h1.3l-.7 .6zM52.7 87.6h1.3"/>
<path d="M52.7 94.2h1.3M53.3 86.4v.6M53.3 87.6v.7M53.3 93v.6M53.3 94.2v.7M53.6 98.4v.7M54.9 98.4v.7M60.5 82l.5 .4 .5-.4M60.5 82.3l.5-.3 .5 .3M60.7 92.1l.5 .3 .5-.3M60.7 92.3l.5-.3 .5 .3M61.2 82l.5 .4 .5-.4"/>
<path d="M61.2 82.3l.5-.3 .5 .3M61.5 92.1l.5 .3 .5-.3M61.5 92.3l.5-.3 .5 .3M63.5 83.8h2.5M63.5 86.4h2.5M63.5 96.5h2.5M63.5 94h2.5M166.4 90.2v1.2h-1.3l1.3 1.3 1.2-1.3h-1.2M166.4 90.2h.1M48.9 102.2h1.9v1.3h4.4v-1.3h1.9M49.5 109.2v2.6M53.3 109.2v2.6"/>
<path d="M57.1 109.2v2.6M60.5 102.2l.5 .4 .5-.4M60.5 102.5l.5-.3 .5 .3M61.2 102.2l.5 .4 .5-.4M61.2 102.5l.5-.3 .5 .3M63.5 104.1h2.5M63.5 106.7h2.5M36.8 174h1.3M43.2 174h1.2M36.8 180.3h1.3M43.2 180.3h1.2M49.5 199.4v1.3h-1.2l1.2 1.2 1.3-1.2h-1.3"/>
<path d="M49.5 199.4h.1M57.1 199.4v1.3h-1.2l1.2 1.2 1.3-1.2h-1.3M57.1 199.4h.1"/>
</g>
<path d="M59.3 85.3h3.6M60.7 95.4h2.2M60.4 105.6h2.5" fill="none" stroke="#006464" stroke-width=".18"/>
<path d="M38.1 173h5.1v2h-5.1zM38.1 179.3h5.1v2.1h-5.1z" fill="none" stroke="#840000" stroke-width=".25"/>
<path d="M153.7 81.3h10.1v17.8h-10.1z" fill="#ffffc2"/>
<g fill="none" stroke="#840000" stroke-width=".18">
<path d="M151.1 96.5h2.6M151.1 94h2.6M151.1 90.2h2.6M151.1 86.4h2.6M151.1 83.8h2.6M153.7 81.3h10.1v17.8h-10.1zM163.8 96.5h2.6M163.8 94h2.6M163.8 90.2h2.6M163.8 86.4h2.6M163.8 83.8h2.6M44.4 141v1.2h-1.2l1.2 1.3 1.3-1.3h-1.3"/>
<path d="M44.4 141h.1M254 198.1v1.3h-1.3l1.3 1.3 1.3-1.3h-1.3M254 198.1h.1"/>
</g>
<path d="M47 167.6h16.5v29.3h-16.5z" fill="#00c200"/>
<g fill="none" stroke="#840000" stroke-width=".18">
<path d="M44.4 174h2.6M44.4 176.5h2.6M47 167.6h16.5v29.3h-16.5zM52.7 174.6h1.3l-.7 .7zM52.7 175.3h1.3M53.3 165.1v2.5M53.3 174v.6M53.3 175.3v.6M60.5 169.7l.5 .3 .5-.3M60.5 169.9l.5-.3 .5 .3M60.7 179.7l.5 .3 .5-.3M60.7 180l.5-.4 .5 .4"/>
<path d="M61.2 169.7l.5 .3 .5-.3M61.2 169.9l.5-.3 .5 .3M61.5 179.7l.5 .3 .5-.3M61.5 180l.5-.4 .5 .4M63.5 171.5h2.5M63.5 174h2.5M44.4 182.9v1.3h-1.2l1.2 1.2 1.3-1.2h-1.3M44.4 182.9h.1M44.4 180.3h2.6M44.4 182.9h2.6M48.9 186.1h8.2v5.7h-8.2zM48.9 189.9h1.9v1.2h4.4v-1.2h1.9"/>
<path d="M49.5 196.9v2.5M51.1 186.1v.6M52.3 186.1v.6M52.7 181.2h1.3l-.7 .7zM52.7 181.9h1.3M53.3 199.4v1.3h-1.2l1.2 1.2 1.3-1.2h-1.3M53.3 199.4h.1M53.3 180.6v.6M53.3 181.9v.6M53.3 196.9v2.5M53.6 186.1v.6M54.9 186.1v.6"/>
<path d="M57.1 196.9v2.5M60.5 189.9l.5 .3 .5-.3M60.5 190.1l.5-.3 .5 .3M61.2 189.9l.5 .3 .5-.3M61.2 190.1l.5-.3 .5 .3M63.5 191.8h2.5M63.5 194.3h2.5M63.5 184.2h2.5M63.5 181.6h2.5"/>
</g>
<path d="M59.3 172.9h3.6M60.4 193.2h2.5M60.7 183h2.2" fill="none" stroke="#006464" stroke-width=".18"/>
<path d="M78.7 168.9h10.2v17.8h-10.2z" fill="#ffffc2"/>
<g fill="none" stroke="#840000" stroke-width=".18">
<path d="M76.2 171.5h2.5M76.2 174h2.5M76.2 177.8h2.5M78.7 168.9h10.2v17.8h-10.2zM88.9 171.5h2.5M88.9 174h2.5M88.9 177.8h2.5M76.2 181.6h2.5M76.2 184.2h2.5M88.9 181.6h2.5M88.9 184.2h2.5M34.3 231.1h.1"/>
<path d="M34.3 238.8v1.2h-1.3l1.3 1.3 1.3-1.3h-1.3M34.3 238.8h.1M34.3 228.6l-.8 1.3M34.3 228.6l.8 1.3M34.3 228.6v10.2M43.2 231.1h.1M43.2 228.6l-.8 1.3M43.2 228.6l.7 1.3M43.2 228.6v10.2"/>
</g>
<path d="M33 232.4l2.6 5.1h-2.6l2.6-5.1zM35.6 234.4v.5h-2.6v.6M41.9 232.4l2.5 5.1h-2.5l2.5-5.1zM44.4 234.4v.5h-2.5v.6" fill="none" stroke="#840000" stroke-width=".25"/>
<path d="M285.7 39.4h35.6v158.7h-35.6z" fill="#ffffc2"/>
<g fill="none" stroke="#840000" stroke-width=".18">
<path d="M285.7 39.4h35.6v158.7h-35.6zM281.9 54.6h3.8M281.9 57.2h3.8M281.9 59.7h3.8M281.9 52.1h3.8M281.9 49.5h3.8M281.9 69.9h3.8M281.9 67.3h3.8M281.9 62.2h3.8M281.9 77.5h3.8M281.9 72.4h3.8M281.9 74.9h3.8"/>
<path d="M281.9 95.3h3.8M281.9 97.8h3.8M281.9 90.2h3.8M281.9 92.7h3.8M281.9 85.1h3.8M281.9 87.6h3.8M281.9 80h3.8M281.9 105.4h3.8M281.9 102.9h3.8M281.9 115.6h3.8M281.9 113h3.8M281.9 108h3.8"/>
<path d="M281.9 110.5h3.8M281.9 138.4h3.8M281.9 125.7h3.8M281.9 128.3h3.8M281.9 133.4h3.8M281.9 123.2h3.8M281.9 130.8h3.8M281.9 120.7h3.8M281.9 141h3.8M281.9 151.1h3.8M281.9 158.8h3.8M281.9 148.6h3.8"/>
<path d="M281.9 146.1h3.8M281.9 156.2h3.8M281.9 143.5h3.8M281.9 161.3h3.8M281.9 163.8h3.8M281.9 168.9h3.8M281.9 166.4h3.8M281.9 176.5h3.8M281.9 174h3.8M281.9 179.1h3.8M281.9 191.8h3.8M281.9 186.7h3.8"/>
<path d="M281.9 181.6h3.8M281.9 184.2h3.8M281.9 194.3h3.8"/>
</g>
<path d="M339.1 39.4h35.5v138.4h-35.5z" fill="#ffffc2"/>
<g fill="none" stroke="#840000" stroke-width=".18">
<path d="M339.1 39.4h35.5v138.4h-35.5zM335.3 49.5h3.8M335.3 52.1h3.8M335.3 54.6h3.8M335.3 57.2h3.8M335.3 59.7h3.8M335.3 77.5h3.8M335.3 67.3h3.8M335.3 72.4h3.8M335.3 69.9h3.8M335.3 74.9h3.8M335.3 62.2h3.8"/>
<path d="M151.1 90.2v1.2h-1.2l1.2 1.3 1.3-1.3h-1.3M151.1 90.2h.1M335.3 80h3.8M335.3 85.1h3.8M335.3 87.6h3.8M335.3 95.3h3.8M335.3 90.2h3.8M335.3 97.8h3.8M335.3 92.7h3.8M335.3 108h3.8M335.3 102.9h3.8M335.3 105.4h3.8"/>
<path d="M335.3 110.5h3.8M335.3 113h3.8M335.3 115.6h3.8M335.3 130.8h3.8M335.3 133.4h3.8M335.3 138.4h3.8M335.3 125.7h3.8M335.3 120.7h3.8M335.3 123.2h3.8M335.3 128.3h3.8M335.3 156.2h3.8M335.3 158.8h3.8"/>
<path d="M335.3 148.6h3.8M335.3 143.5h3.8M335.3 146.1h3.8M335.3 141h3.8M335.3 151.1h3.8M186.7 174h1.3M193 174h1.3M194.3 176.5v1.3h-1.3l1.3 1.3 1.3-1.3h-1.3M194.3 176.5h.1M335.3 171.5h3.8M335.3 174h3.8M335.3 168.9h3.8"/>
<path d="M335.3 161.3h3.8M335.3 163.8h3.8M186.7 180.3h1.3M193 180.3h1.3M194.3 182.9v1.3h-1.3l1.3 1.2 1.3-1.2h-1.3M194.3 182.9h.1M43.2 238.8v1.2h-1.3l1.3 1.3 1.2-1.3h-1.2M43.2 238.8h.1M52.1 238.8v1.2h-1.3l1.3 1.3 1.2-1.3h-1.2M52.1 238.8h.1M52.1 231.1h.1M52.1 228.6v10.2"/>
<path d="M52.1 228.6l-.8 1.3M52.1 228.6l.7 1.3M61 231.1h.1M61 238.8v1.2h-1.3l1.3 1.3 1.2-1.3h-1.2M61 238.8h.1M61 228.6l-.8 1.3M61 228.6l.7 1.3M61 228.6v10.2M69.8 231.1h.1M69.8 238.8v1.2h-1.2l1.2 1.3 1.3-1.3h-1.3M69.8 238.8h.1M69.8 228.6v10.2"/>
<path d="M69.8 228.6l-.7 1.3M69.8 228.6l.8 1.3M78.7 231.1h.1M78.7 238.8v1.2h-1.2l1.2 1.3 1.3-1.3h-1.3M78.7 238.8h.1M78.7 228.6v10.2M78.7 228.6l-.7 1.3M78.7 228.6l.8 1.3M87.6 238.8v1.2h-1.2l1.2 1.3 1.3-1.3h-1.3M87.6 238.8h.1M87.6 231.1h.1M87.6 228.6v10.2"/>
<path d="M87.6 228.6l-.7 1.3M87.6 228.6l.8 1.3M96.5 231.1h.1M96.5 238.8v1.2h-1.3l1.3 1.3 1.3-1.3h-1.3M96.5 238.8h.1M96.5 228.6l-.7 1.3M96.5 228.6l.8 1.3M96.5 228.6v10.2M105.4 238.8v1.2h-1.3l1.3 1.3 1.3-1.3h-1.3M105.4 238.8h.1M105.4 231.1h.1M105.4 228.6v10.2"/>
<path d="M105.4 228.6l-.8 1.3M105.4 228.6l.8 1.3"/>
</g>
<g fill="none" stroke="#840000" stroke-width=".25">
<path d="M188 173h5v2h-5zM188 179.3h5v2.1h-5zM50.8 232.4l2.5 5.1h-2.5l2.5-5.1zM53.3 234.4v.5h-2.5v.6M59.7 232.4l2.5 5.1h-2.5l2.5-5.1zM62.2 234.4v.5h-2.5v.6M68.6 232.4l2.5 5.1h-2.5l2.5-5.1zM71.1 234.4v.5h-2.5v.6M77.5 232.4l2.5 5.1h-2.5l2.5-5.1zM80 234.4v.5h-2.5v.6M86.4 232.4l2.5 5.1h-2.5l2.5-5.1zM88.9 234.4v.5h-2.5v.6"/>
<path d="M95.2 232.4l2.6 5.1h-2.6l2.6-5.1zM97.8 234.4v.5h-2.6v.6M104.1 232.4l2.6 5.1h-2.6l2.6-5.1zM106.7 234.4v.5h-2.6v.6"/>
</g>
<path d="M153.7 168.9h10.1v17.8h-10.1z" fill="#ffffc2"/>
<path d="M151.1 177.8h2.6M151.1 174h2.6M151.1 171.5h2.6M153.7 168.9h10.1v17.8h-10.1zM163.8 177.8h2.6M163.8 174h2.6M163.8 171.5h2.6M151.1 184.2h2.6M151.1 181.6h2.6M163.8 184.2h2.6M163.8 181.6h2.6" fill="none" stroke="#840000" stroke-width=".18"/>
<path d="M153.7 189.2h10.1v17.8h-10.1z" fill="#ffffc2"/>
<path d="M151.1 194.3h2.6M151.1 191.8h2.6M151.1 198.1h2.6M153.7 189.2h10.1v17.8h-10.1zM163.8 194.3h2.6M163.8 191.8h2.6M163.8 198.1h2.6M151.1 204.5h2.6M151.1 201.9h2.6M163.8 204.5h2.6M163.8 201.9h2.6" fill="none" stroke="#840000" stroke-width=".18"/>
<path d="M241.3 189.2h10.2v17.8h-10.2z" fill="#ffffc2"/>
<g fill="none" stroke="#840000" stroke-width=".18">
<path d="M166.4 198.1v1.3h-1.3l1.3 1.3 1.2-1.3h-1.2M166.4 198.1h.1M238.8 194.3h2.5M238.8 191.8h2.5M238.8 198.1h2.5M241.3 189.2h10.2v17.8h-10.2zM251.5 194.3h2.5M251.5 191.8h2.5M251.5 198.1h2.5M238.8 201.9h2.5M238.8 204.5h2.5M251.5 201.9h2.5"/>
<path d="M251.5 204.5h2.5"/>
</g>
<path d="M196.8 167.6h16.6v29.3h-16.6z" fill="#00c200"/>
<g fill="none" stroke="#840000" stroke-width=".18">
<path d="M199.4 111.8v1.2h-1.3l1.3 1.3 1.3-1.3h-1.3M199.4 111.8h.1M203.2 111.8v1.2h-1.3l1.3 1.3 1.3-1.3h-1.3M203.2 111.8h.1M207 111.8v1.2h-1.3l1.3 1.3 1.3-1.3h-1.3M207 111.8h.1M186.7 132.1h1.3M193 132.1h1.3M203.2 123.2h.1M203.2 120.7v2.5M203.2 120.7l-.8 1.2M203.2 120.7l.8 1.2"/>
<path d="M124.5 157.5v1.3h-1.3l1.3 1.2 1.2-1.2h-1.2M124.5 157.5h.1M128.3 157.5v1.3h-1.3l1.3 1.2 1.2-1.2h-1.2M128.3 157.5h.1M132.1 157.5v1.3h-1.3l1.3 1.2 1.2-1.2h-1.2M132.1 157.5h.1M128.3 165.1h.1M128.3 162.6l-.8 1.2M128.3 162.6l.7 1.2M128.3 162.6v2.5M151.1 177.8v1.3h-1.2l1.2 1.2 1.3-1.2h-1.3M151.1 177.8h.1"/>
<path d="M166.4 177.8v1.3h-1.3l1.3 1.2 1.2-1.2h-1.2M166.4 177.8h.1M194.3 174h2.5M194.3 176.5h2.5M196.8 167.6h16.6v29.3h-16.6zM202.6 174.6h1.2l-.6 .7zM202.6 175.3h1.2M203.2 165.1h.1M203.2 162.6v5M203.2 174v.6M203.2 175.3v.6M203.2 162.6l-.8 1.2"/>
<path d="M203.2 162.6l.8 1.2M210.3 169.7l.5 .3 .5-.3M210.3 169.9l.5-.3 .5 .3M210.6 179.7l.5 .3 .5-.3M210.6 180l.5-.4 .5 .4M211.1 169.7l.5 .3 .5-.3M211.1 169.9l.5-.3 .5 .3M211.3 179.7l.5 .3 .5-.3M211.3 180l.5-.4 .5 .4M213.4 171.5h2.5M213.4 174h2.5M194.3 180.3h2.5"/>
<path d="M194.3 182.9h2.5M198.8 186.1h8.2v5.7h-8.2zM198.8 189.9h1.9v1.2h4.4v-1.2h1.9M199.4 196.9v2.5M200.9 186.1v.6M202.2 186.1v.6M202.6 181.2h1.2l-.6 .7zM202.6 181.9h1.2M203.2 180.6v.6M203.2 181.9v.6M203.2 196.9v2.5M203.5 186.1v.6"/>
<path d="M204.7 186.1v.6M207 199.4v1.3h-1.3l1.3 1.2 1.3-1.2h-1.3M207 199.4h.1M207 196.9v2.5M210.3 189.9l.5 .3 .5-.3M210.3 190.1l.5-.3 .5 .3M211.1 189.9l.5 .3 .5-.3M211.1 190.1l.5-.3 .5 .3M213.4 191.8h2.5M213.4 194.3h2.5M213.4 184.2h2.5M213.4 181.6h2.5"/>
</g>
<path d="M209.2 172.9h3.5M210.3 193.2h2.4M210.6 183h2.1" fill="none" stroke="#006464" stroke-width=".18"/>
<path d="M188 131.1h5v2h-5z" fill="none" stroke="#840000" stroke-width=".25"/>
<path d="M121.9 125.7h16.5v29.2h-16.5z" fill="#00c200"/>
<g fill="none" stroke="#840000" stroke-width=".18">
<path d="M119.4 134.6v1.3h-1.3l1.3 1.3 1.2-1.3h-1.2M119.4 134.6h.1M119.4 132.1h2.5M119.4 134.6h2.5M119.4 138.4h2.5M121.9 125.7h16.5v29.2h-16.5zM127.6 132.7h1.3l-.6 .7zM127.6 139.3h1.3l-.6 .7zM127.6 133.4h1.3M127.6 140h1.3M128.3 123.2v2.5M128.3 132.1v.6"/>
<path d="M128.3 133.4v.6M128.3 138.7v.6M128.3 140v.6M135.4 127.8l.5 .3 .5-.3M135.4 128l.5-.3 .5 .3M135.6 137.8l.5 .3 .6-.3M135.6 138l.5-.3 .6 .3M136.1 127.8l.6 .3 .5-.3M136.1 128l.6-.3 .5 .3M136.4 137.8l.5 .3 .5-.3M136.4 138l.5-.3 .5 .3M138.4 129.5h2.6"/>
<path d="M138.4 132.1h2.6M138.4 139.7h2.6M119.4 141v1.2h-1.3l1.3 1.3 1.2-1.3h-1.2M119.4 141h.1M119.4 141h2.5M123.8 144.1h8.3v5.8h-8.3zM123.8 148h1.9v1.2h4.5v-1.2h1.9M124.5 154.9v2.6M126 144.1v.7M127.3 144.1v.7M128.3 154.9v2.6M128.5 144.1v.7"/>
<path d="M129.8 144.1v.7M132.1 154.9v2.6M135.4 148l.5 .3 .5-.3M135.4 148.2l.5-.3 .5 .3M136.1 148l.6 .3 .5-.3M136.1 148.2l.6-.3 .5 .3M138.4 149.9h2.6M138.4 152.4h2.6M138.4 142.2h2.6M194.3 141v1.2h-1.3l1.3 1.3 1.3-1.3h-1.3M194.3 141h.1"/>
</g>
<path d="M134.3 131h3.5M135.4 151.3h2.4M135.7 141.1h2.1" fill="none" stroke="#006464" stroke-width=".18"/>
<path d="M153.7 127h10.1v17.8h-10.1z" fill="#ffffc2"/>
<g fill="none" stroke="#840000" stroke-width=".18">
<path d="M151.1 110.5v1.3h-1.2l1.2 1.2 1.3-1.2h-1.3M151.1 110.5h.1M151.1 135.9v1.3h-1.2l1.2 1.2 1.3-1.2h-1.3M151.1 135.9h.1M151.1 139.7h2.6M151.1 135.9h2.6M151.1 132.1h2.6M151.1 129.5h2.6M153.7 127h10.1v17.8h-10.1zM163.8 139.7h2.6M163.8 135.9h2.6M163.8 132.1h2.6"/>
<path d="M163.8 129.5h2.6M166.4 135.9v1.3h-1.3l1.3 1.2 1.2-1.2h-1.2M166.4 135.9h.1M151.1 142.2h2.6M163.8 142.2h2.6"/>
</g>
<path d="M153.7 101.6h10.1v17.8h-10.1z" fill="#ffffc2"/>
<g fill="none" stroke="#840000" stroke-width=".18">
<path d="M151.1 106.7h2.6M151.1 104.1h2.6M151.1 110.5h2.6M151.1 116.8h2.6M151.1 114.3h2.6M153.7 101.6h10.1v17.8h-10.1zM163.8 106.7h2.6M163.8 104.1h2.6M163.8 110.5h2.6M163.8 116.8h2.6M163.8 114.3h2.6M166.4 110.5v1.3h-1.3l1.3 1.2 1.2-1.2h-1.2"/>
<path d="M166.4 110.5h.1M151.1 156.2v1.3h-1.2l1.2 1.3 1.3-1.3h-1.3M151.1 156.2h.1"/>
</g>
<path d="M153.7 147.3h10.1v17.8h-10.1z" fill="#ffffc2"/>
<g fill="none" stroke="#840000" stroke-width=".18">
<path d="M380.5 53.3h7l1.1 1.3-1.1 1.3h-7zM380.5 55.9h7l1.1 1.3-1.1 1.2h-7zM53.3 77.5h.1M53.3 77.5v2.5M128.3 77.5h.1M128.3 77.5v2.5M203.2 77.5h.1M203.2 77.5v2.5M28.7 91.4h7l1.1 1.3-1.1 1.3h-7zM28.7 85.1h7l1.1 1.3-1.1 1.2h-7zM36.8 92.7h1.3M36.8 86.4h1.3"/>
<path d="M43.2 92.7h3.8M43.2 86.4h3.8M44.4 95.3h.1M44.4 88.9h.1M44.4 88.9h2.6M44.4 95.3h2.6M63.5 86.4h2.5M63.5 83.8h2.5M63.5 96.5h2.5M63.5 94h2.5M76.2 90.2h.1M76.2 86.4h2.5"/>
<path d="M76.2 83.8h2.5M76.2 96.5h2.5M76.2 94h2.5M76.2 90.2h2.5M88.9 86.4h2.5M88.9 83.8h2.5M88.9 96.5h2.5M88.9 94h2.5M88.9 90.2h2.5M91.4 90.2h.1M103.6 91.4h7l1.2 1.3-1.2 1.3h-7zM103.6 85.1h7l1.2 1.3-1.2 1.2h-7z"/>
<path d="M111.8 92.7h1.2M111.8 86.4h1.2M118.1 92.7h3.8M118.1 86.4h3.8M119.4 88.9h.1M119.4 95.3h.1M119.4 88.9h2.5M119.4 95.3h2.5M138.4 86.4h2.6M138.4 83.8h2.6M138.4 96.5h2.6M138.4 94h2.6"/>
<path d="M151.1 90.2h.1M151.1 86.4h2.6M151.1 83.8h2.6M151.1 96.5h2.6M151.1 94h2.6M151.1 90.2h2.6M163.8 86.4h2.6M163.8 83.8h2.6M163.8 96.5h2.6M163.8 94h2.6M163.8 90.2h2.6M166.4 90.2h.1"/>
<path d="M178.6 85.1h7l1.1 1.3-1.1 1.2h-7zM178.6 91.4h7l1.1 1.3-1.1 1.3h-7zM186.7 92.7h1.3M186.7 86.4h1.3M193 92.7h3.8M193 86.4h3.8M194.3 88.9h.1M194.3 95.3h.1M194.3 88.9h2.5M194.3 95.3h2.5M213.4 86.4h2.5M213.4 83.8h2.5"/>
<path d="M213.4 96.5h2.5M213.4 94h2.5M226.1 90.2h.1M226.1 86.4h2.5M226.1 83.8h2.5M226.1 96.5h2.5M226.1 94h2.5M226.1 90.2h2.5M238.8 86.4h2.5M238.8 83.8h2.5M238.8 96.5h2.5M238.8 94h2.5"/>
<path d="M238.8 90.2h2.5M241.3 90.2h.1M273.8 88.9h7l1.1 1.3-1.1 1.2h-7zM273.8 91.4h7l1.1 1.3-1.1 1.3h-7zM327.1 96.5h7.1l1.1 1.3-1.1 1.3h-7.1zM327.1 91.4h7.1l1.1 1.3-1.1 1.3h-7.1zM327.1 88.9h7.1l1.1 1.3-1.1 1.2h-7.1zM380.5 88.9h7l1.1 1.3-1.1 1.2h-7zM380.5 91.4h7l1.1 1.3-1.1 1.3h-7zM49.5 111.8h.1M49.5 109.2v2.6M53.3 111.8h.1"/>
<path d="M53.3 109.2v2.6M57.1 111.8h.1M57.1 109.2v2.6M63.5 104.1h2.5M63.5 106.7h2.5M76.2 110.5h.1M76.2 104.1h2.5M76.2 106.7h2.5M76.2 110.5h2.5M76.2 114.3h2.5M76.2 116.8h2.5M88.9 104.1h2.5"/>
<path d="M88.9 106.7h2.5M88.9 110.5h2.5M88.9 114.3h2.5M88.9 116.8h2.5M91.4 110.5h.1M124.5 111.8h.1M124.5 109.2v2.6M128.3 111.8h.1M128.3 109.2v2.6M132.1 111.8h.1M132.1 109.2v2.6M138.4 104.1h2.6"/>
<path d="M138.4 106.7h2.6M151.1 110.5h.1M151.1 104.1h2.6M151.1 106.7h2.6M151.1 110.5h2.6M151.1 114.3h2.6M151.1 116.8h2.6M163.8 104.1h2.6M163.8 106.7h2.6M163.8 110.5h2.6M163.8 114.3h2.6M163.8 116.8h2.6"/>
<path d="M166.4 110.5h.1M199.4 111.8h.1M199.4 109.2v2.6M203.2 111.8h.1M203.2 109.2v2.6M207 111.8h.1M207 109.2v2.6M213.4 104.1h2.5M213.4 106.7h2.5M226.1 110.5h.1M226.1 104.1h2.5M226.1 106.7h2.5"/>
<path d="M226.1 110.5h2.5M226.1 114.3h2.5M226.1 116.8h2.5M238.8 104.1h2.5M238.8 106.7h2.5M238.8 110.5h2.5M238.8 114.3h2.5M238.8 116.8h2.5M241.3 110.5h.1M327.1 101.6h7.1l1.1 1.3-1.1 1.2h-7.1zM327.1 104.1h7.1l1.1 1.3-1.1 1.3h-7.1zM327.1 106.7h7.1l1.1 1.3-1.1 1.2h-7.1z"/>
<path d="M28.7 130.8h7l1.1 1.3-1.1 1.3h-7zM28.7 137.2h7l1.1 1.2-1.1 1.3h-7zM36.8 132.1h1.3M36.8 138.4h1.3M43.2 132.1h3.8M43.2 138.4h3.8M44.4 134.6h.1M44.4 134.6h2.6M53.3 123.2h.1M53.3 123.2v2.5M63.5 139.7h2.5M63.5 132.1h2.5"/>
<path d="M63.5 129.5h2.5M76.2 135.9h.1M76.2 139.7h2.5M76.2 135.9h2.5M76.2 132.1h2.5M76.2 129.5h2.5M88.9 139.7h2.5M88.9 135.9h2.5M88.9 132.1h2.5M88.9 129.5h2.5M91.4 135.9h.1M103.6 137.2h7l1.2 1.2-1.2 1.3h-7z"/>
<path d="M103.6 130.8h7l1.2 1.3-1.2 1.3h-7zM111.8 132.1h1.2M111.8 138.4h1.2M118.1 132.1h3.8M118.1 138.4h3.8M119.4 134.6h.1M119.4 134.6h2.5M128.3 123.2h.1M128.3 123.2v2.5M138.4 139.7h2.6M138.4 132.1h2.6M138.4 129.5h2.6"/>
<path d="M151.1 135.9h.1M151.1 139.7h2.6M151.1 135.9h2.6M151.1 132.1h2.6M151.1 129.5h2.6M163.8 139.7h2.6M163.8 135.9h2.6M163.8 132.1h2.6M163.8 129.5h2.6M166.4 135.9h.1M178.6 130.8h7l1.1 1.3-1.1 1.3h-7zM178.6 137.2h7l1.1 1.2-1.1 1.3h-7z"/>
<path d="M186.7 132.1h1.3M186.7 138.4h1.3M193 132.1h3.8M193 138.4h3.8M194.3 134.6h.1M194.3 134.6h2.5M203.2 123.2h.1M203.2 123.2v2.5M213.4 139.7h2.5M213.4 132.1h2.5M213.4 129.5h2.5M226.1 135.9h.1"/>
<path d="M226.1 139.7h2.5M226.1 135.9h2.5M226.1 132.1h2.5M226.1 129.5h2.5M238.8 139.7h2.5M238.8 135.9h2.5M238.8 132.1h2.5M238.8 129.5h2.5M241.3 135.9h.1M380.5 124.5h7l1.1 1.2-1.1 1.3h-7zM380.5 121.9h7l1.1 1.3-1.1 1.3h-7zM44.4 141h.1"/>
<path d="M44.4 141h2.6M49.5 157.5h.1M49.5 154.9v2.6M53.3 157.5h.1M53.3 154.9v2.6M57.1 157.5h.1M57.1 154.9v2.6M63.5 152.4h2.5M63.5 149.9h2.5M63.5 142.2h2.5M76.2 156.2h.1M76.2 152.4h2.5"/>
<path d="M76.2 149.9h2.5M76.2 156.2h2.5M76.2 142.2h2.5M88.9 152.4h2.5M88.9 149.9h2.5M88.9 156.2h2.5M88.9 142.2h2.5M91.4 156.2v1.3h-1.2l1.2 1.3 1.3-1.3h-1.3M91.4 156.2h.1M119.4 141h.1M119.4 141h2.5M124.5 157.5h.1"/>
<path d="M124.5 154.9v2.6M128.3 157.5h.1M128.3 154.9v2.6M132.1 157.5h.1M132.1 154.9v2.6M138.4 152.4h2.6M138.4 149.9h2.6M138.4 142.2h2.6M151.1 156.2h.1M151.1 152.4h2.6M151.1 149.9h2.6M151.1 156.2h2.6"/>
<path d="M151.1 142.2h2.6M153.7 147.3h10.1v17.8h-10.1zM163.8 152.4h2.6M163.8 149.9h2.6M163.8 156.2h2.6M163.8 142.2h2.6M166.4 156.2v1.3h-1.3l1.3 1.3 1.2-1.3h-1.2M166.4 156.2h.1M194.3 141h.1M194.3 141h2.5M199.4 157.5h.1M199.4 154.9v2.6"/>
<path d="M203.2 157.5h.1M203.2 154.9v2.6M207 157.5h.1M207 154.9v2.6M213.4 152.4h2.5M213.4 149.9h2.5M213.4 142.2h2.5M226.1 156.2h.1M226.1 152.4h2.5M226.1 149.9h2.5M226.1 156.2h2.5M226.1 142.2h2.5"/>
<path d="M238.8 152.4h2.5M238.8 149.9h2.5M238.8 156.2h2.5M238.8 142.2h2.5M241.3 156.2h.1M28.7 172.7h7l1.1 1.3-1.1 1.3h-7zM28.7 179.1h7l1.1 1.2-1.1 1.3h-7zM36.8 174h1.3M43.2 174h3.8M44.4 176.5h.1M44.4 176.5h2.6M53.3 165.1h.1"/>
<path d="M53.3 165.1v2.5M63.5 174h2.5M63.5 171.5h2.5M76.2 177.8h.1M76.2 160h2.5M76.2 162.6h2.5M76.2 174h2.5M76.2 177.8h2.5M76.2 171.5h2.5M88.9 160h2.5M88.9 162.6h2.5M88.9 174h2.5"/>
<path d="M88.9 177.8h2.5M88.9 171.5h2.5M91.4 177.8v1.3h-1.2l1.2 1.2 1.3-1.2h-1.3M91.4 177.8h.1M103.6 179.1h7l1.2 1.2-1.2 1.3h-7zM103.6 172.7h7l1.2 1.3-1.2 1.3h-7zM111.8 174h1.2M118.1 174h3.8M119.4 176.5v1.3h-1.3l1.3 1.3 1.2-1.3h-1.2M119.4 176.5h.1M119.4 176.5h2.5M128.3 165.1h.1"/>
<path d="M128.3 165.1v2.5M138.4 174h2.6M138.4 171.5h2.6M151.1 177.8h.1M151.1 160h2.6M151.1 162.6h2.6M151.1 174h2.6M151.1 177.8h2.6M151.1 171.5h2.6M163.8 160h2.6M163.8 162.6h2.6M163.8 174h2.6"/>
<path d="M163.8 177.8h2.6M163.8 171.5h2.6M166.4 177.8h.1M178.6 179.1h7l1.1 1.2-1.1 1.3h-7zM178.6 172.7h7l1.1 1.3-1.1 1.3h-7zM186.7 174h1.3M193 174h3.8M194.3 176.5h.1M194.3 176.5h2.5M203.2 165.1h.1M203.2 165.1v2.5M213.4 174h2.5"/>
<path d="M213.4 171.5h2.5M226.1 160h2.5M226.1 162.6h2.5M238.8 177.8h.1M238.8 160h2.5M238.8 162.6h2.5M238.8 174h2.5M238.8 177.8h2.5M238.8 171.5h2.5M251.5 174h2.5M251.5 177.8h2.5M251.5 171.5h2.5"/>
<path d="M254 177.8h.1M327.1 162.6h7.1l1.1 1.2-1.1 1.3h-7.1zM327.1 160h7.1l1.1 1.3-1.1 1.3h-7.1zM380.5 172.7h7l1.1 1.3-1.1 1.3h-7zM380.5 175.3h7l1.1 1.2-1.1 1.3h-7zM36.8 180.3h1.3M43.2 180.3h3.8M44.4 182.9h.1M44.4 182.9h2.6M49.5 199.4h.1M49.5 196.9v2.5M53.3 199.4h.1"/>
<path d="M53.3 196.9v2.5M57.1 199.4h.1M57.1 196.9v2.5M63.5 181.6h2.5M63.5 184.2h2.5M63.5 191.8h2.5M63.5 194.3h2.5M76.2 198.1h.1M76.2 181.6h2.5M76.2 184.2h2.5M76.2 191.8h2.5M76.2 194.3h2.5"/>
<path d="M76.2 198.1h2.5M88.9 181.6h2.5M88.9 184.2h2.5M88.9 191.8h2.5M88.9 194.3h2.5M88.9 198.1h2.5M91.4 198.1h.1M111.8 180.3h1.2M118.1 180.3h3.8M119.4 182.9h.1M119.4 182.9h2.5M124.5 199.4h.1"/>
<path d="M124.5 196.9v2.5M128.3 199.4h.1M128.3 196.9v2.5M132.1 199.4h.1M132.1 196.9v2.5M138.4 181.6h2.6M138.4 184.2h2.6M138.4 191.8h2.6M138.4 194.3h2.6M151.1 198.1h.1M151.1 181.6h2.6M151.1 184.2h2.6"/>
<path d="M151.1 191.8h2.6M151.1 194.3h2.6M151.1 198.1h2.6M163.8 181.6h2.6M163.8 184.2h2.6M163.8 191.8h2.6M163.8 194.3h2.6M163.8 198.1h2.6M166.4 198.1h.1M186.7 180.3h1.3M193 180.3h3.8M194.3 182.9h.1"/>
<path d="M194.3 182.9h2.5M199.4 199.4h.1M199.4 196.9v2.5M203.2 199.4h.1M203.2 196.9v2.5M207 199.4h.1M207 196.9v2.5M213.4 181.6h2.5M213.4 184.2h2.5M213.4 191.8h2.5M213.4 194.3h2.5M238.8 198.1h.1"/>
<path d="M238.8 181.6h2.5M238.8 184.2h2.5M238.8 191.8h2.5M238.8 194.3h2.5M238.8 198.1h2.5M251.5 181.6h2.5M251.5 184.2h2.5M251.5 191.8h2.5M251.5 194.3h2.5M251.5 198.1h2.5M254 198.1h.1M76.2 201.9h2.5"/>
<path d="M76.2 204.5h2.5M88.9 201.9h2.5M88.9 204.5h2.5M151.1 201.9h2.6M151.1 204.5h2.6M163.8 201.9h2.6M163.8 204.5h2.6M238.8 201.9h2.5M238.8 204.5h2.5M251.5 201.9h2.5M251.5 204.5h2.5M34.3 238.8h.1"/>
<path d="M34.3 231.1h.1M34.3 231.1v2.6M34.3 236.2v2.6M43.2 238.8h.1M43.2 231.1h.1M43.2 231.1v2.6M43.2 236.2v2.6M52.1 231.1h.1M52.1 238.8h.1M52.1 231.1v2.6M52.1 236.2v2.6M61 238.8h.1"/>
<path d="M61 231.1h.1M61 231.1v2.6M61 236.2v2.6M69.8 238.8h.1M69.8 231.1h.1M69.8 231.1v2.6M69.8 236.2v2.6M78.7 238.8h.1M78.7 231.1h.1M78.7 231.1v2.6M78.7 236.2v2.6M87.6 231.1h.1"/>
<path d="M87.6 238.8h.1M87.6 231.1v2.6M87.6 236.2v2.6M96.5 238.8h.1M96.5 231.1h.1M96.5 231.1v2.6M96.5 236.2v2.6M105.4 231.1h.1M105.4 238.8h.1M105.4 231.1v2.6M105.4 236.2v2.6M130.8 236.2h.1"/>
<path d="M130.8 233.7v2.5M138.4 236.2h.1M138.4 233.7v2.5M146 236.2h.1M146 233.7v2.5M153.7 236.2h.1M153.7 233.7v2.5"/>
</g>
<path d="M113 179.3h5.1v2.1h-5.1zM113 173h5.1v2h-5.1z" fill="none" stroke="#840000" stroke-width=".25"/>
<g fill="none" stroke="#009600" stroke-width=".18">
<path d="M325.1 59.7h10.2M325.1 52.1h10.2M325.1 49.5h10.2M378.5 59.7h10.1M325.1 62.2h10.2M325.1 74.9h10.2M325.1 72.4h10.2M378.5 62.2h10.1M66 83.8h10.2M66 86.4h10.2M66 94h10.2M66 96.5h10.2"/>
<path d="M91.4 83.8h10.2M91.4 86.4h10.2M91.4 94h10.2M91.4 96.5h10.2M141 83.8h10.1M141 86.4h10.1M141 94h10.1M141 96.5h10.1M166.4 83.8h10.1M166.4 86.4h10.1M166.4 94h10.1M166.4 96.5h10.1"/>
<path d="M215.9 83.8h10.2M215.9 86.4h10.2M215.9 94h10.2M215.9 96.5h10.2M241.3 83.8h10.2M241.3 86.4h10.2M241.3 94h10.2M241.3 96.5h10.2M378.5 85.1h10.1M378.5 87.6h10.1M378.5 97.8h10.1M378.5 95.3h10.1"/>
<path d="M66 104.1h10.2M66 106.7h10.2M91.4 104.1h10.2M91.4 106.7h10.2M141 104.1h10.1M141 106.7h10.1M166.4 104.1h10.1M166.4 106.7h10.1M215.9 104.1h10.2M215.9 106.7h10.2M241.3 104.1h10.2M241.3 106.7h10.2"/>
<path d="M271.8 102.9h10.1M271.8 105.4h10.1M325.1 115.6h10.2M325.1 113h10.2M378.5 102.9h10.1M378.5 105.4h10.1M66 129.5h10.2M66 139.7h10.2M66 132.1h10.2M91.4 129.5h10.2M91.4 139.7h10.2M91.4 132.1h10.2"/>
<path d="M141 129.5h10.1M141 139.7h10.1M141 132.1h10.1M166.4 129.5h10.1M166.4 139.7h10.1M166.4 132.1h10.1M215.9 129.5h10.2M215.9 139.7h10.2M215.9 132.1h10.2M241.3 129.5h10.2M241.3 139.7h10.2M241.3 132.1h10.2"/>
<path d="M325.1 123.2h10.2M325.1 120.7h10.2M325.1 130.8h10.2M325.1 128.3h10.2M325.1 125.7h10.2M325.1 138.4h10.2M325.1 133.4h10.2M378.5 130.8h10.1M378.5 133.4h10.1M66 142.2h10.2M66 149.9h10.2M66 152.4h10.2"/>
<path d="M91.4 142.2h10.2M91.4 149.9h10.2M91.4 152.4h10.2M141 142.2h10.1M141 149.9h10.1M141 152.4h10.1M166.4 142.2h10.1M166.4 149.9h10.1M166.4 152.4h10.1M215.9 142.2h10.2M215.9 149.9h10.2M215.9 152.4h10.2"/>
<path d="M241.3 142.2h10.2M241.3 149.9h10.2M241.3 152.4h10.2M271.8 151.1h10.1M271.8 148.6h10.1M325.1 151.1h10.2M325.1 148.6h10.2M325.1 141h10.2M66 171.5h10.2M66 174h10.2M91.4 171.5h10.2M91.4 174h10.2"/>
<path d="M141 171.5h10.1M141 174h10.1M166.4 171.5h10.1M166.4 174h10.1M215.9 171.5h22.9M215.9 174h22.9M254 171.5h10.2M254 174h10.2M271.8 166.4h10.1M271.8 161.3h10.1M271.8 168.9h10.1M271.8 163.8h10.1"/>
<path d="M271.8 179.1h10.1M378.5 166.4h10.1M378.5 161.3h10.1M378.5 168.9h10.1M378.5 163.8h10.1M66 184.2h10.2M66 181.6h10.2M66 194.3h10.2M66 191.8h10.2M91.4 184.2h10.2M91.4 181.6h10.2M91.4 194.3h10.2"/>
<path d="M91.4 191.8h10.2M141 184.2h10.1M141 181.6h10.1M141 194.3h10.1M141 191.8h10.1M166.4 184.2h10.1M166.4 181.6h10.1M166.4 194.3h10.1M166.4 191.8h10.1M215.9 184.2h8.9M215.9 181.6h8.9M215.9 194.3h8.9"/>
<path d="M215.9 191.8h8.9M228.6 184.2h10.2M228.6 181.6h10.2M228.6 194.3h10.2M228.6 191.8h10.2M254 184.2h10.2M254 181.6h10.2M254 194.3h10.2M254 191.8h10.2M271.8 181.6h10.1"/>
</g>
<g fill="none" stroke="#000084" stroke-width=".18">
<path d="M281.3 59.1l1.2 1.2M281.3 54l1.2 1.2M281.3 51.5l1.2 1.2M281.3 56.5l1.2 1.3M281.3 48.9l1.2 1.2M282.5 59.1l-1.2 1.2M282.5 54l-1.2 1.2M282.5 51.5l-1.2 1.2M282.5 56.5l-1.2 1.3M282.5 48.9l-1.2 1.2M334.7 54l1.2 1.2M334.7 56.5l1.2 1.3"/>
<path d="M335.9 54l-1.2 1.2M335.9 56.5l-1.2 1.3M388 48.9l1.2 1.2M388 51.5l1.2 1.2M389.2 51.5l-1.2 1.2M389.2 48.9l-1.2 1.2M281.3 79.4l1.2 1.2M281.3 76.9l1.2 1.2M281.3 66.7l1.2 1.2M281.3 61.6l1.2 1.2M281.3 71.8l1.2 1.2M281.3 74.3l1.2 1.2"/>
<path d="M281.3 69.2l1.2 1.3M282.5 79.4l-1.2 1.2M282.5 76.9l-1.2 1.2M282.5 66.7l-1.2 1.2M282.5 61.6l-1.2 1.2M282.5 71.8l-1.2 1.2M282.5 74.3l-1.2 1.2M282.5 69.2l-1.2 1.3M334.7 76.9l1.2 1.2M334.7 79.4l1.2 1.2M334.7 66.7l1.2 1.2M334.7 69.2l1.2 1.3"/>
<path d="M335.9 76.9l-1.2 1.2M335.9 66.7l-1.2 1.2M335.9 79.4l-1.2 1.2M335.9 69.2l-1.2 1.3M388 69.2l1.2 1.3M388 66.7l1.2 1.2M388 79.4l1.2 1.2M388 76.9l1.2 1.2M388 74.3l1.2 1.2M388 71.8l1.2 1.2M389.2 69.2l-1.2 1.3M389.2 66.7l-1.2 1.2"/>
<path d="M389.2 79.4l-1.2 1.2M389.2 76.9l-1.2 1.2M389.2 74.3l-1.2 1.2M389.2 71.8l-1.2 1.2M281.3 84.5l1.2 1.2M281.3 97.2l1.2 1.2M281.3 87l1.2 1.2M281.3 94.6l1.2 1.3M282.5 84.5l-1.2 1.2M282.5 97.2l-1.2 1.2M282.5 87l-1.2 1.2M282.5 94.6l-1.2 1.3"/>
<path d="M334.7 84.5l1.2 1.2M334.7 94.6l1.2 1.3M334.7 87l1.2 1.2M335.9 84.5l-1.2 1.2M335.9 94.6l-1.2 1.3M335.9 87l-1.2 1.2M75.6 113.7l1.2 1.2M75.6 116.2l1.2 1.2M76.8 113.7l-1.2 1.2M76.8 116.2l-1.2 1.2M90.8 113.7l1.2 1.2M90.8 116.2l1.2 1.2"/>
<path d="M92 113.7l-1.2 1.2M92 116.2l-1.2 1.2M150.5 113.7l1.2 1.2M150.5 116.2l1.2 1.2M151.7 113.7l-1.2 1.2M151.7 116.2l-1.2 1.2M165.8 113.7l1.2 1.2M165.8 116.2l1.2 1.2M167 113.7l-1.2 1.2M167 116.2l-1.2 1.2M225.5 113.7l1.2 1.2M225.5 116.2l1.2 1.2"/>
<path d="M226.7 113.7l-1.2 1.2M226.7 116.2l-1.2 1.2M240.7 113.7l1.2 1.2M240.7 116.2l1.2 1.2M241.9 113.7l-1.2 1.2M241.9 116.2l-1.2 1.2M281.3 112.4l1.2 1.2M281.3 109.9l1.2 1.2M281.3 107.3l1.2 1.3M281.3 115l1.2 1.2M282.5 112.4l-1.2 1.2M282.5 109.9l-1.2 1.2"/>
<path d="M282.5 107.3l-1.2 1.3M282.5 115l-1.2 1.2M334.7 109.9l1.2 1.2M335.9 109.9l-1.2 1.2M388 107.3l1.2 1.3M388 112.4l1.2 1.2M388 109.9l1.2 1.2M388 115l1.2 1.2M389.2 107.3l-1.2 1.3M389.2 112.4l-1.2 1.2M389.2 109.9l-1.2 1.2M389.2 115l-1.2 1.2"/>
<path d="M281.3 120l1.2 1.3M281.3 127.7l1.2 1.2M281.3 125.1l1.2 1.2M281.3 132.7l1.2 1.3M281.3 137.8l1.2 1.2M281.3 130.2l1.2 1.2M281.3 122.6l1.2 1.2M282.5 130.2l-1.2 1.2M282.5 120l-1.2 1.3M282.5 127.7l-1.2 1.2M282.5 125.1l-1.2 1.2M282.5 132.7l-1.2 1.3"/>
<path d="M282.5 137.8l-1.2 1.2M282.5 122.6l-1.2 1.2M388 127.7l1.2 1.2M388 120l1.2 1.3M388 137.8l1.2 1.2M389.2 127.7l-1.2 1.2M389.2 120l-1.2 1.3M389.2 137.8l-1.2 1.2M75.6 159.4l1.2 1.2M76.8 159.4l-1.2 1.2M90.8 159.4l1.2 1.2M92 159.4l-1.2 1.2"/>
<path d="M150.5 159.4l1.2 1.2M151.7 159.4l-1.2 1.2M165.8 159.4l1.2 1.2M167 159.4l-1.2 1.2M225.5 159.4l1.2 1.2M226.7 159.4l-1.2 1.2M240.7 159.4l1.2 1.2M241.9 159.4l-1.2 1.2M281.3 140.4l1.2 1.2M281.3 142.9l1.2 1.2M281.3 155.6l1.2 1.2M281.3 158.1l1.2 1.3"/>
<path d="M281.3 145.4l1.2 1.3M282.5 140.4l-1.2 1.2M282.5 142.9l-1.2 1.2M282.5 155.6l-1.2 1.2M282.5 158.1l-1.2 1.3M282.5 145.4l-1.2 1.3M334.7 142.9l1.2 1.2M334.7 155.6l1.2 1.2M334.7 158.1l1.2 1.3M334.7 145.4l1.2 1.3M335.9 142.9l-1.2 1.2M335.9 155.6l-1.2 1.2"/>
<path d="M335.9 158.1l-1.2 1.3M335.9 145.4l-1.2 1.3M388 158.1l1.2 1.3M388 155.6l1.2 1.2M388 150.5l1.2 1.2M388 140.4l1.2 1.2M388 145.4l1.2 1.3M388 148l1.2 1.2M388 142.9l1.2 1.2M389.2 158.1l-1.2 1.3M389.2 155.6l-1.2 1.2M389.2 150.5l-1.2 1.2"/>
<path d="M389.2 140.4l-1.2 1.2M389.2 145.4l-1.2 1.3M389.2 148l-1.2 1.2M389.2 142.9l-1.2 1.2M75.6 162l1.2 1.2M76.8 162l-1.2 1.2M90.8 162l1.2 1.2M92 162l-1.2 1.2M150.5 162l1.2 1.2M151.7 162l-1.2 1.2M165.8 162l1.2 1.2M167 162l-1.2 1.2"/>
<path d="M225.5 162l1.2 1.2M226.7 162l-1.2 1.2M240.7 162l1.2 1.2M241.9 162l-1.2 1.2M281.3 175.9l1.2 1.2M281.3 173.4l1.2 1.2M282.5 175.9l-1.2 1.2M282.5 173.4l-1.2 1.2M334.7 170.8l1.2 1.3M334.7 173.4l1.2 1.2M334.7 168.3l1.2 1.2M335.9 173.4l-1.2 1.2"/>
<path d="M335.9 170.8l-1.2 1.3M335.9 168.3l-1.2 1.2M388 178.5l1.2 1.2M389.2 178.5l-1.2 1.2M281.3 193.7l1.2 1.2M281.3 183.5l1.2 1.3M281.3 186.1l1.2 1.2M281.3 191.2l1.2 1.2M282.5 193.7l-1.2 1.2M282.5 183.5l-1.2 1.3M282.5 186.1l-1.2 1.2M282.5 191.2l-1.2 1.2"/>
<path d="M388 183.5l1.2 1.3M388 193.7l1.2 1.2M388 181l1.2 1.2M388 186.1l1.2 1.2M388 191.2l1.2 1.2M389.2 183.5l-1.2 1.3M389.2 193.7l-1.2 1.2M389.2 181l-1.2 1.2M389.2 186.1l-1.2 1.2M389.2 191.2l-1.2 1.2M75.6 201.3l1.2 1.2M75.6 203.9l1.2 1.2"/>
<path d="M76.8 201.3l-1.2 1.2M76.8 203.9l-1.2 1.2M90.8 201.3l1.2 1.2M90.8 203.9l1.2 1.2M92 201.3l-1.2 1.2M92 203.9l-1.2 1.2M150.5 201.3l1.2 1.2M150.5 203.9l1.2 1.2M151.7 201.3l-1.2 1.2M151.7 203.9l-1.2 1.2M165.8 203.9l1.2 1.2M165.8 201.3l1.2 1.2"/>
<path d="M167 203.9l-1.2 1.2M167 201.3l-1.2 1.2M238.2 203.9l1.2 1.2M238.2 201.3l1.2 1.2M239.4 203.9l-1.2 1.2M239.4 201.3l-1.2 1.2M253.4 203.9l1.2 1.2M253.4 201.3l1.2 1.2M254.6 203.9l-1.2 1.2M254.6 201.3l-1.2 1.2"/>
</g>
<path d="M22.9 66h245.1v148.6h-245.1zM22.9 219.7h92.7v27.9h-92.7zM121.9 221h40.7v24.1h-40.7z" fill="none" stroke="#0000c2" stroke-width=".18" stroke-dasharray="1.7 .6"/>
<g fill="none" stroke="#006464" stroke-width=".18">
<path d="M59.3 85.3h3.6M60.7 95.4h2.2M134.3 85.3h3.5M135.7 95.4h2.1M209.2 85.3h3.5M210.6 95.4h2.1M60.4 105.6h2.5M135.4 105.6h2.4M210.3 105.6h2.4M59.3 131h3.6M134.3 131h3.5M209.2 131h3.5"/>
<path d="M60.4 151.3h2.5M60.7 141.1h2.2M135.4 151.3h2.4M135.7 141.1h2.1M210.3 151.3h2.4M210.6 141.1h2.1M59.3 172.9h3.6M134.3 172.9h3.5M209.2 172.9h3.5M60.4 193.2h2.5M60.7 183h2.2M135.4 193.2h2.4"/>
<path d="M135.7 183h2.1M210.3 193.2h2.4M210.6 183h2.1"/>
</g>
<use href="#words"/>
</svg>
